VERSION 5.8 ;
BUSBITCHARS "[]" ;
DIVIDERCHAR "/" ;
UNITS
    DATABASE MICRONS 1000 ;
END UNITS

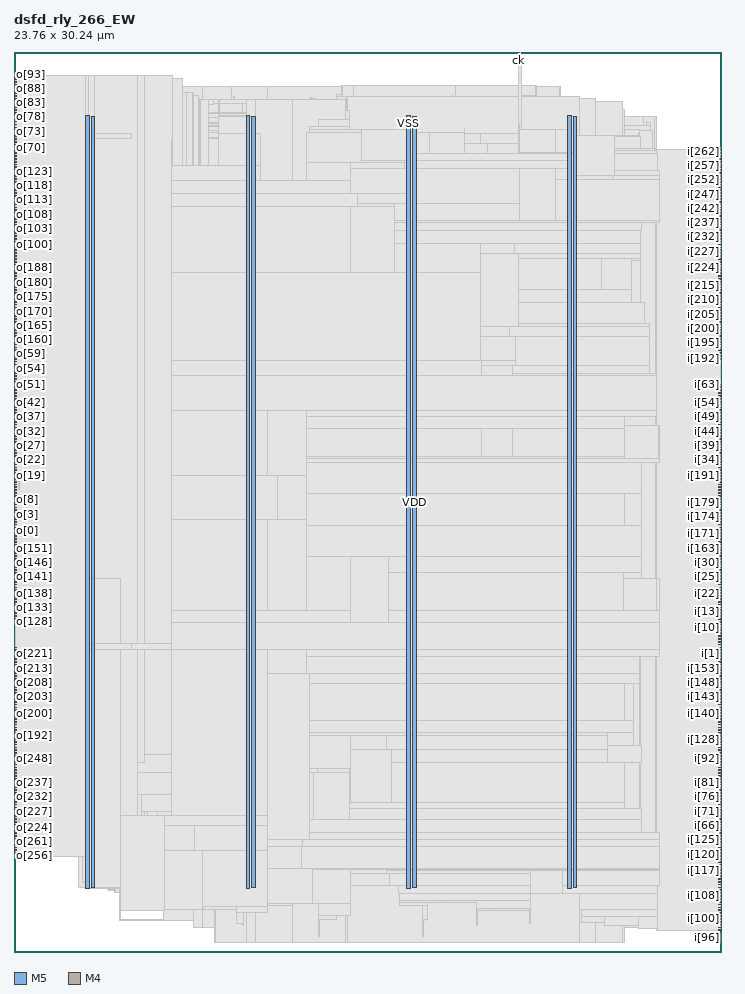
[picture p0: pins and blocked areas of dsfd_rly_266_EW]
MACRO dsfd_rly_266_EW
  FOREIGN dsfd_rly_266_EW 0 0 ;
  CLASS BLOCK ;
  SIZE 23.76 BY 30.24 ;
  PIN ck
    DIRECTION INPUT ;
    USE SIGNAL ;
    PORT
      LAYER M5 ;
        RECT  16.944 30.156 16.968 30.24 ;
    END
  END ck
  PIN i[0]
    DIRECTION INPUT ;
    USE SIGNAL ;
    PORT
      LAYER M4 ;
        RECT  23.676 9.936 23.76 9.96 ;
    END
  END i[0]
  PIN i[100]
    DIRECTION INPUT ;
    USE SIGNAL ;
    PORT
      LAYER M4 ;
        RECT  23.676 1.104 23.76 1.128 ;
    END
  END i[100]
  PIN i[101]
    DIRECTION INPUT ;
    USE SIGNAL ;
    PORT
      LAYER M4 ;
        RECT  23.676 1.2 23.76 1.224 ;
    END
  END i[101]
  PIN i[102]
    DIRECTION INPUT ;
    USE SIGNAL ;
    PORT
      LAYER M4 ;
        RECT  23.676 1.296 23.76 1.32 ;
    END
  END i[102]
  PIN i[103]
    DIRECTION INPUT ;
    USE SIGNAL ;
    PORT
      LAYER M4 ;
        RECT  23.676 1.392 23.76 1.416 ;
    END
  END i[103]
  PIN i[104]
    DIRECTION INPUT ;
    USE SIGNAL ;
    PORT
      LAYER M4 ;
        RECT  23.676 1.488 23.76 1.512 ;
    END
  END i[104]
  PIN i[105]
    DIRECTION INPUT ;
    USE SIGNAL ;
    PORT
      LAYER M4 ;
        RECT  23.676 1.584 23.76 1.608 ;
    END
  END i[105]
  PIN i[106]
    DIRECTION INPUT ;
    USE SIGNAL ;
    PORT
      LAYER M4 ;
        RECT  23.676 1.68 23.76 1.704 ;
    END
  END i[106]
  PIN i[107]
    DIRECTION INPUT ;
    USE SIGNAL ;
    PORT
      LAYER M4 ;
        RECT  23.676 1.776 23.76 1.8 ;
    END
  END i[107]
  PIN i[108]
    DIRECTION INPUT ;
    USE SIGNAL ;
    PORT
      LAYER M4 ;
        RECT  23.676 1.872 23.76 1.896 ;
    END
  END i[108]
  PIN i[109]
    DIRECTION INPUT ;
    USE SIGNAL ;
    PORT
      LAYER M4 ;
        RECT  23.676 1.968 23.76 1.992 ;
    END
  END i[109]
  PIN i[10]
    DIRECTION INPUT ;
    USE SIGNAL ;
    PORT
      LAYER M4 ;
        RECT  23.676 10.896 23.76 10.92 ;
    END
  END i[10]
  PIN i[110]
    DIRECTION INPUT ;
    USE SIGNAL ;
    PORT
      LAYER M4 ;
        RECT  23.676 2.064 23.76 2.088 ;
    END
  END i[110]
  PIN i[111]
    DIRECTION INPUT ;
    USE SIGNAL ;
    PORT
      LAYER M4 ;
        RECT  23.676 2.16 23.76 2.184 ;
    END
  END i[111]
  PIN i[112]
    DIRECTION INPUT ;
    USE SIGNAL ;
    PORT
      LAYER M4 ;
        RECT  23.676 2.256 23.76 2.28 ;
    END
  END i[112]
  PIN i[113]
    DIRECTION INPUT ;
    USE SIGNAL ;
    PORT
      LAYER M4 ;
        RECT  23.676 2.352 23.76 2.376 ;
    END
  END i[113]
  PIN i[114]
    DIRECTION INPUT ;
    USE SIGNAL ;
    PORT
      LAYER M4 ;
        RECT  23.676 2.448 23.76 2.472 ;
    END
  END i[114]
  PIN i[115]
    DIRECTION INPUT ;
    USE SIGNAL ;
    PORT
      LAYER M4 ;
        RECT  23.676 2.544 23.76 2.568 ;
    END
  END i[115]
  PIN i[116]
    DIRECTION INPUT ;
    USE SIGNAL ;
    PORT
      LAYER M4 ;
        RECT  23.676 2.64 23.76 2.664 ;
    END
  END i[116]
  PIN i[117]
    DIRECTION INPUT ;
    USE SIGNAL ;
    PORT
      LAYER M4 ;
        RECT  23.676 2.736 23.76 2.76 ;
    END
  END i[117]
  PIN i[118]
    DIRECTION INPUT ;
    USE SIGNAL ;
    PORT
      LAYER M4 ;
        RECT  23.676 2.832 23.76 2.856 ;
    END
  END i[118]
  PIN i[119]
    DIRECTION INPUT ;
    USE SIGNAL ;
    PORT
      LAYER M4 ;
        RECT  23.676 2.928 23.76 2.952 ;
    END
  END i[119]
  PIN i[11]
    DIRECTION INPUT ;
    USE SIGNAL ;
    PORT
      LAYER M4 ;
        RECT  23.676 10.992 23.76 11.016 ;
    END
  END i[11]
  PIN i[120]
    DIRECTION INPUT ;
    USE SIGNAL ;
    PORT
      LAYER M4 ;
        RECT  23.676 3.024 23.76 3.048 ;
    END
  END i[120]
  PIN i[121]
    DIRECTION INPUT ;
    USE SIGNAL ;
    PORT
      LAYER M4 ;
        RECT  23.676 3.12 23.76 3.144 ;
    END
  END i[121]
  PIN i[122]
    DIRECTION INPUT ;
    USE SIGNAL ;
    PORT
      LAYER M4 ;
        RECT  23.676 3.216 23.76 3.24 ;
    END
  END i[122]
  PIN i[123]
    DIRECTION INPUT ;
    USE SIGNAL ;
    PORT
      LAYER M4 ;
        RECT  23.676 3.312 23.76 3.336 ;
    END
  END i[123]
  PIN i[124]
    DIRECTION INPUT ;
    USE SIGNAL ;
    PORT
      LAYER M4 ;
        RECT  23.676 3.408 23.76 3.432 ;
    END
  END i[124]
  PIN i[125]
    DIRECTION INPUT ;
    USE SIGNAL ;
    PORT
      LAYER M4 ;
        RECT  23.676 3.504 23.76 3.528 ;
    END
  END i[125]
  PIN i[126]
    DIRECTION INPUT ;
    USE SIGNAL ;
    PORT
      LAYER M4 ;
        RECT  23.676 3.6 23.76 3.624 ;
    END
  END i[126]
  PIN i[127]
    DIRECTION INPUT ;
    USE SIGNAL ;
    PORT
      LAYER M4 ;
        RECT  23.676 3.696 23.76 3.72 ;
    END
  END i[127]
  PIN i[128]
    DIRECTION INPUT ;
    USE SIGNAL ;
    PORT
      LAYER M4 ;
        RECT  23.676 6.864 23.76 6.888 ;
    END
  END i[128]
  PIN i[129]
    DIRECTION INPUT ;
    USE SIGNAL ;
    PORT
      LAYER M4 ;
        RECT  23.676 6.96 23.76 6.984 ;
    END
  END i[129]
  PIN i[12]
    DIRECTION INPUT ;
    USE SIGNAL ;
    PORT
      LAYER M4 ;
        RECT  23.676 11.088 23.76 11.112 ;
    END
  END i[12]
  PIN i[130]
    DIRECTION INPUT ;
    USE SIGNAL ;
    PORT
      LAYER M4 ;
        RECT  23.676 7.056 23.76 7.08 ;
    END
  END i[130]
  PIN i[131]
    DIRECTION INPUT ;
    USE SIGNAL ;
    PORT
      LAYER M4 ;
        RECT  23.676 7.152 23.76 7.176 ;
    END
  END i[131]
  PIN i[132]
    DIRECTION INPUT ;
    USE SIGNAL ;
    PORT
      LAYER M4 ;
        RECT  23.676 7.248 23.76 7.272 ;
    END
  END i[132]
  PIN i[133]
    DIRECTION INPUT ;
    USE SIGNAL ;
    PORT
      LAYER M4 ;
        RECT  23.676 7.344 23.76 7.368 ;
    END
  END i[133]
  PIN i[134]
    DIRECTION INPUT ;
    USE SIGNAL ;
    PORT
      LAYER M4 ;
        RECT  23.676 7.44 23.76 7.464 ;
    END
  END i[134]
  PIN i[135]
    DIRECTION INPUT ;
    USE SIGNAL ;
    PORT
      LAYER M4 ;
        RECT  23.676 7.536 23.76 7.56 ;
    END
  END i[135]
  PIN i[136]
    DIRECTION INPUT ;
    USE SIGNAL ;
    PORT
      LAYER M4 ;
        RECT  23.676 7.632 23.76 7.656 ;
    END
  END i[136]
  PIN i[137]
    DIRECTION INPUT ;
    USE SIGNAL ;
    PORT
      LAYER M4 ;
        RECT  23.676 7.728 23.76 7.752 ;
    END
  END i[137]
  PIN i[138]
    DIRECTION INPUT ;
    USE SIGNAL ;
    PORT
      LAYER M4 ;
        RECT  23.676 7.824 23.76 7.848 ;
    END
  END i[138]
  PIN i[139]
    DIRECTION INPUT ;
    USE SIGNAL ;
    PORT
      LAYER M4 ;
        RECT  23.676 7.92 23.76 7.944 ;
    END
  END i[139]
  PIN i[13]
    DIRECTION INPUT ;
    USE SIGNAL ;
    PORT
      LAYER M4 ;
        RECT  23.676 11.184 23.76 11.208 ;
    END
  END i[13]
  PIN i[140]
    DIRECTION INPUT ;
    USE SIGNAL ;
    PORT
      LAYER M4 ;
        RECT  23.676 8.016 23.76 8.04 ;
    END
  END i[140]
  PIN i[141]
    DIRECTION INPUT ;
    USE SIGNAL ;
    PORT
      LAYER M4 ;
        RECT  23.676 8.112 23.76 8.136 ;
    END
  END i[141]
  PIN i[142]
    DIRECTION INPUT ;
    USE SIGNAL ;
    PORT
      LAYER M4 ;
        RECT  23.676 8.208 23.76 8.232 ;
    END
  END i[142]
  PIN i[143]
    DIRECTION INPUT ;
    USE SIGNAL ;
    PORT
      LAYER M4 ;
        RECT  23.676 8.304 23.76 8.328 ;
    END
  END i[143]
  PIN i[144]
    DIRECTION INPUT ;
    USE SIGNAL ;
    PORT
      LAYER M4 ;
        RECT  23.676 8.4 23.76 8.424 ;
    END
  END i[144]
  PIN i[145]
    DIRECTION INPUT ;
    USE SIGNAL ;
    PORT
      LAYER M4 ;
        RECT  23.676 8.496 23.76 8.52 ;
    END
  END i[145]
  PIN i[146]
    DIRECTION INPUT ;
    USE SIGNAL ;
    PORT
      LAYER M4 ;
        RECT  23.676 8.592 23.76 8.616 ;
    END
  END i[146]
  PIN i[147]
    DIRECTION INPUT ;
    USE SIGNAL ;
    PORT
      LAYER M4 ;
        RECT  23.676 8.688 23.76 8.712 ;
    END
  END i[147]
  PIN i[148]
    DIRECTION INPUT ;
    USE SIGNAL ;
    PORT
      LAYER M4 ;
        RECT  23.676 8.784 23.76 8.808 ;
    END
  END i[148]
  PIN i[149]
    DIRECTION INPUT ;
    USE SIGNAL ;
    PORT
      LAYER M4 ;
        RECT  23.676 8.88 23.76 8.904 ;
    END
  END i[149]
  PIN i[14]
    DIRECTION INPUT ;
    USE SIGNAL ;
    PORT
      LAYER M4 ;
        RECT  23.676 11.28 23.76 11.304 ;
    END
  END i[14]
  PIN i[150]
    DIRECTION INPUT ;
    USE SIGNAL ;
    PORT
      LAYER M4 ;
        RECT  23.676 8.976 23.76 9 ;
    END
  END i[150]
  PIN i[151]
    DIRECTION INPUT ;
    USE SIGNAL ;
    PORT
      LAYER M4 ;
        RECT  23.676 9.072 23.76 9.096 ;
    END
  END i[151]
  PIN i[152]
    DIRECTION INPUT ;
    USE SIGNAL ;
    PORT
      LAYER M4 ;
        RECT  23.676 9.168 23.76 9.192 ;
    END
  END i[152]
  PIN i[153]
    DIRECTION INPUT ;
    USE SIGNAL ;
    PORT
      LAYER M4 ;
        RECT  23.676 9.264 23.76 9.288 ;
    END
  END i[153]
  PIN i[154]
    DIRECTION INPUT ;
    USE SIGNAL ;
    PORT
      LAYER M4 ;
        RECT  23.676 9.36 23.76 9.384 ;
    END
  END i[154]
  PIN i[155]
    DIRECTION INPUT ;
    USE SIGNAL ;
    PORT
      LAYER M4 ;
        RECT  23.676 9.456 23.76 9.48 ;
    END
  END i[155]
  PIN i[156]
    DIRECTION INPUT ;
    USE SIGNAL ;
    PORT
      LAYER M4 ;
        RECT  23.676 9.552 23.76 9.576 ;
    END
  END i[156]
  PIN i[157]
    DIRECTION INPUT ;
    USE SIGNAL ;
    PORT
      LAYER M4 ;
        RECT  23.676 9.648 23.76 9.672 ;
    END
  END i[157]
  PIN i[158]
    DIRECTION INPUT ;
    USE SIGNAL ;
    PORT
      LAYER M4 ;
        RECT  23.676 9.744 23.76 9.768 ;
    END
  END i[158]
  PIN i[159]
    DIRECTION INPUT ;
    USE SIGNAL ;
    PORT
      LAYER M4 ;
        RECT  23.676 9.84 23.76 9.864 ;
    END
  END i[159]
  PIN i[15]
    DIRECTION INPUT ;
    USE SIGNAL ;
    PORT
      LAYER M4 ;
        RECT  23.676 11.376 23.76 11.4 ;
    END
  END i[15]
  PIN i[160]
    DIRECTION INPUT ;
    USE SIGNAL ;
    PORT
      LAYER M4 ;
        RECT  23.676 13.008 23.76 13.032 ;
    END
  END i[160]
  PIN i[161]
    DIRECTION INPUT ;
    USE SIGNAL ;
    PORT
      LAYER M4 ;
        RECT  23.676 13.104 23.76 13.128 ;
    END
  END i[161]
  PIN i[162]
    DIRECTION INPUT ;
    USE SIGNAL ;
    PORT
      LAYER M4 ;
        RECT  23.676 13.2 23.76 13.224 ;
    END
  END i[162]
  PIN i[163]
    DIRECTION INPUT ;
    USE SIGNAL ;
    PORT
      LAYER M4 ;
        RECT  23.676 13.296 23.76 13.32 ;
    END
  END i[163]
  PIN i[164]
    DIRECTION INPUT ;
    USE SIGNAL ;
    PORT
      LAYER M4 ;
        RECT  23.676 13.392 23.76 13.416 ;
    END
  END i[164]
  PIN i[165]
    DIRECTION INPUT ;
    USE SIGNAL ;
    PORT
      LAYER M4 ;
        RECT  23.676 13.488 23.76 13.512 ;
    END
  END i[165]
  PIN i[166]
    DIRECTION INPUT ;
    USE SIGNAL ;
    PORT
      LAYER M4 ;
        RECT  23.676 13.584 23.76 13.608 ;
    END
  END i[166]
  PIN i[167]
    DIRECTION INPUT ;
    USE SIGNAL ;
    PORT
      LAYER M4 ;
        RECT  23.676 13.68 23.76 13.704 ;
    END
  END i[167]
  PIN i[168]
    DIRECTION INPUT ;
    USE SIGNAL ;
    PORT
      LAYER M4 ;
        RECT  23.676 13.776 23.76 13.8 ;
    END
  END i[168]
  PIN i[169]
    DIRECTION INPUT ;
    USE SIGNAL ;
    PORT
      LAYER M4 ;
        RECT  23.676 13.872 23.76 13.896 ;
    END
  END i[169]
  PIN i[16]
    DIRECTION INPUT ;
    USE SIGNAL ;
    PORT
      LAYER M4 ;
        RECT  23.676 11.472 23.76 11.496 ;
    END
  END i[16]
  PIN i[170]
    DIRECTION INPUT ;
    USE SIGNAL ;
    PORT
      LAYER M4 ;
        RECT  23.676 13.968 23.76 13.992 ;
    END
  END i[170]
  PIN i[171]
    DIRECTION INPUT ;
    USE SIGNAL ;
    PORT
      LAYER M4 ;
        RECT  23.676 14.064 23.76 14.088 ;
    END
  END i[171]
  PIN i[172]
    DIRECTION INPUT ;
    USE SIGNAL ;
    PORT
      LAYER M4 ;
        RECT  23.676 14.16 23.76 14.184 ;
    END
  END i[172]
  PIN i[173]
    DIRECTION INPUT ;
    USE SIGNAL ;
    PORT
      LAYER M4 ;
        RECT  23.676 14.256 23.76 14.28 ;
    END
  END i[173]
  PIN i[174]
    DIRECTION INPUT ;
    USE SIGNAL ;
    PORT
      LAYER M4 ;
        RECT  23.676 14.352 23.76 14.376 ;
    END
  END i[174]
  PIN i[175]
    DIRECTION INPUT ;
    USE SIGNAL ;
    PORT
      LAYER M4 ;
        RECT  23.676 14.448 23.76 14.472 ;
    END
  END i[175]
  PIN i[176]
    DIRECTION INPUT ;
    USE SIGNAL ;
    PORT
      LAYER M4 ;
        RECT  23.676 14.544 23.76 14.568 ;
    END
  END i[176]
  PIN i[177]
    DIRECTION INPUT ;
    USE SIGNAL ;
    PORT
      LAYER M4 ;
        RECT  23.676 14.64 23.76 14.664 ;
    END
  END i[177]
  PIN i[178]
    DIRECTION INPUT ;
    USE SIGNAL ;
    PORT
      LAYER M4 ;
        RECT  23.676 14.736 23.76 14.76 ;
    END
  END i[178]
  PIN i[179]
    DIRECTION INPUT ;
    USE SIGNAL ;
    PORT
      LAYER M4 ;
        RECT  23.676 14.832 23.76 14.856 ;
    END
  END i[179]
  PIN i[17]
    DIRECTION INPUT ;
    USE SIGNAL ;
    PORT
      LAYER M4 ;
        RECT  23.676 11.568 23.76 11.592 ;
    END
  END i[17]
  PIN i[180]
    DIRECTION INPUT ;
    USE SIGNAL ;
    PORT
      LAYER M4 ;
        RECT  23.676 14.928 23.76 14.952 ;
    END
  END i[180]
  PIN i[181]
    DIRECTION INPUT ;
    USE SIGNAL ;
    PORT
      LAYER M4 ;
        RECT  23.676 15.024 23.76 15.048 ;
    END
  END i[181]
  PIN i[182]
    DIRECTION INPUT ;
    USE SIGNAL ;
    PORT
      LAYER M4 ;
        RECT  23.676 15.12 23.76 15.144 ;
    END
  END i[182]
  PIN i[183]
    DIRECTION INPUT ;
    USE SIGNAL ;
    PORT
      LAYER M4 ;
        RECT  23.676 15.216 23.76 15.24 ;
    END
  END i[183]
  PIN i[184]
    DIRECTION INPUT ;
    USE SIGNAL ;
    PORT
      LAYER M4 ;
        RECT  23.676 15.312 23.76 15.336 ;
    END
  END i[184]
  PIN i[185]
    DIRECTION INPUT ;
    USE SIGNAL ;
    PORT
      LAYER M4 ;
        RECT  23.676 15.408 23.76 15.432 ;
    END
  END i[185]
  PIN i[186]
    DIRECTION INPUT ;
    USE SIGNAL ;
    PORT
      LAYER M4 ;
        RECT  23.676 15.504 23.76 15.528 ;
    END
  END i[186]
  PIN i[187]
    DIRECTION INPUT ;
    USE SIGNAL ;
    PORT
      LAYER M4 ;
        RECT  23.676 15.6 23.76 15.624 ;
    END
  END i[187]
  PIN i[188]
    DIRECTION INPUT ;
    USE SIGNAL ;
    PORT
      LAYER M4 ;
        RECT  23.676 15.696 23.76 15.72 ;
    END
  END i[188]
  PIN i[189]
    DIRECTION INPUT ;
    USE SIGNAL ;
    PORT
      LAYER M4 ;
        RECT  23.676 15.792 23.76 15.816 ;
    END
  END i[189]
  PIN i[18]
    DIRECTION INPUT ;
    USE SIGNAL ;
    PORT
      LAYER M4 ;
        RECT  23.676 11.664 23.76 11.688 ;
    END
  END i[18]
  PIN i[190]
    DIRECTION INPUT ;
    USE SIGNAL ;
    PORT
      LAYER M4 ;
        RECT  23.676 15.888 23.76 15.912 ;
    END
  END i[190]
  PIN i[191]
    DIRECTION INPUT ;
    USE SIGNAL ;
    PORT
      LAYER M4 ;
        RECT  23.676 15.984 23.76 16.008 ;
    END
  END i[191]
  PIN i[192]
    DIRECTION INPUT ;
    USE SIGNAL ;
    PORT
      LAYER M4 ;
        RECT  23.676 19.92 23.76 19.944 ;
    END
  END i[192]
  PIN i[193]
    DIRECTION INPUT ;
    USE SIGNAL ;
    PORT
      LAYER M4 ;
        RECT  23.676 20.016 23.76 20.04 ;
    END
  END i[193]
  PIN i[194]
    DIRECTION INPUT ;
    USE SIGNAL ;
    PORT
      LAYER M4 ;
        RECT  23.676 20.112 23.76 20.136 ;
    END
  END i[194]
  PIN i[195]
    DIRECTION INPUT ;
    USE SIGNAL ;
    PORT
      LAYER M4 ;
        RECT  23.676 20.208 23.76 20.232 ;
    END
  END i[195]
  PIN i[196]
    DIRECTION INPUT ;
    USE SIGNAL ;
    PORT
      LAYER M4 ;
        RECT  23.676 20.304 23.76 20.328 ;
    END
  END i[196]
  PIN i[197]
    DIRECTION INPUT ;
    USE SIGNAL ;
    PORT
      LAYER M4 ;
        RECT  23.676 20.4 23.76 20.424 ;
    END
  END i[197]
  PIN i[198]
    DIRECTION INPUT ;
    USE SIGNAL ;
    PORT
      LAYER M4 ;
        RECT  23.676 20.496 23.76 20.52 ;
    END
  END i[198]
  PIN i[199]
    DIRECTION INPUT ;
    USE SIGNAL ;
    PORT
      LAYER M4 ;
        RECT  23.676 20.592 23.76 20.616 ;
    END
  END i[199]
  PIN i[19]
    DIRECTION INPUT ;
    USE SIGNAL ;
    PORT
      LAYER M4 ;
        RECT  23.676 11.76 23.76 11.784 ;
    END
  END i[19]
  PIN i[1]
    DIRECTION INPUT ;
    USE SIGNAL ;
    PORT
      LAYER M4 ;
        RECT  23.676 10.032 23.76 10.056 ;
    END
  END i[1]
  PIN i[200]
    DIRECTION INPUT ;
    USE SIGNAL ;
    PORT
      LAYER M4 ;
        RECT  23.676 20.688 23.76 20.712 ;
    END
  END i[200]
  PIN i[201]
    DIRECTION INPUT ;
    USE SIGNAL ;
    PORT
      LAYER M4 ;
        RECT  23.676 20.784 23.76 20.808 ;
    END
  END i[201]
  PIN i[202]
    DIRECTION INPUT ;
    USE SIGNAL ;
    PORT
      LAYER M4 ;
        RECT  23.676 20.88 23.76 20.904 ;
    END
  END i[202]
  PIN i[203]
    DIRECTION INPUT ;
    USE SIGNAL ;
    PORT
      LAYER M4 ;
        RECT  23.676 20.976 23.76 21 ;
    END
  END i[203]
  PIN i[204]
    DIRECTION INPUT ;
    USE SIGNAL ;
    PORT
      LAYER M4 ;
        RECT  23.676 21.072 23.76 21.096 ;
    END
  END i[204]
  PIN i[205]
    DIRECTION INPUT ;
    USE SIGNAL ;
    PORT
      LAYER M4 ;
        RECT  23.676 21.168 23.76 21.192 ;
    END
  END i[205]
  PIN i[206]
    DIRECTION INPUT ;
    USE SIGNAL ;
    PORT
      LAYER M4 ;
        RECT  23.676 21.264 23.76 21.288 ;
    END
  END i[206]
  PIN i[207]
    DIRECTION INPUT ;
    USE SIGNAL ;
    PORT
      LAYER M4 ;
        RECT  23.676 21.36 23.76 21.384 ;
    END
  END i[207]
  PIN i[208]
    DIRECTION INPUT ;
    USE SIGNAL ;
    PORT
      LAYER M4 ;
        RECT  23.676 21.456 23.76 21.48 ;
    END
  END i[208]
  PIN i[209]
    DIRECTION INPUT ;
    USE SIGNAL ;
    PORT
      LAYER M4 ;
        RECT  23.676 21.552 23.76 21.576 ;
    END
  END i[209]
  PIN i[20]
    DIRECTION INPUT ;
    USE SIGNAL ;
    PORT
      LAYER M4 ;
        RECT  23.676 11.856 23.76 11.88 ;
    END
  END i[20]
  PIN i[210]
    DIRECTION INPUT ;
    USE SIGNAL ;
    PORT
      LAYER M4 ;
        RECT  23.676 21.648 23.76 21.672 ;
    END
  END i[210]
  PIN i[211]
    DIRECTION INPUT ;
    USE SIGNAL ;
    PORT
      LAYER M4 ;
        RECT  23.676 21.744 23.76 21.768 ;
    END
  END i[211]
  PIN i[212]
    DIRECTION INPUT ;
    USE SIGNAL ;
    PORT
      LAYER M4 ;
        RECT  23.676 21.84 23.76 21.864 ;
    END
  END i[212]
  PIN i[213]
    DIRECTION INPUT ;
    USE SIGNAL ;
    PORT
      LAYER M4 ;
        RECT  23.676 21.936 23.76 21.96 ;
    END
  END i[213]
  PIN i[214]
    DIRECTION INPUT ;
    USE SIGNAL ;
    PORT
      LAYER M4 ;
        RECT  23.676 22.032 23.76 22.056 ;
    END
  END i[214]
  PIN i[215]
    DIRECTION INPUT ;
    USE SIGNAL ;
    PORT
      LAYER M4 ;
        RECT  23.676 22.128 23.76 22.152 ;
    END
  END i[215]
  PIN i[216]
    DIRECTION INPUT ;
    USE SIGNAL ;
    PORT
      LAYER M4 ;
        RECT  23.676 22.224 23.76 22.248 ;
    END
  END i[216]
  PIN i[217]
    DIRECTION INPUT ;
    USE SIGNAL ;
    PORT
      LAYER M4 ;
        RECT  23.676 22.32 23.76 22.344 ;
    END
  END i[217]
  PIN i[218]
    DIRECTION INPUT ;
    USE SIGNAL ;
    PORT
      LAYER M4 ;
        RECT  23.676 22.416 23.76 22.44 ;
    END
  END i[218]
  PIN i[219]
    DIRECTION INPUT ;
    USE SIGNAL ;
    PORT
      LAYER M4 ;
        RECT  23.676 22.512 23.76 22.536 ;
    END
  END i[219]
  PIN i[21]
    DIRECTION INPUT ;
    USE SIGNAL ;
    PORT
      LAYER M4 ;
        RECT  23.676 11.952 23.76 11.976 ;
    END
  END i[21]
  PIN i[220]
    DIRECTION INPUT ;
    USE SIGNAL ;
    PORT
      LAYER M4 ;
        RECT  23.676 22.608 23.76 22.632 ;
    END
  END i[220]
  PIN i[221]
    DIRECTION INPUT ;
    USE SIGNAL ;
    PORT
      LAYER M4 ;
        RECT  23.676 22.704 23.76 22.728 ;
    END
  END i[221]
  PIN i[222]
    DIRECTION INPUT ;
    USE SIGNAL ;
    PORT
      LAYER M4 ;
        RECT  23.676 22.8 23.76 22.824 ;
    END
  END i[222]
  PIN i[223]
    DIRECTION INPUT ;
    USE SIGNAL ;
    PORT
      LAYER M4 ;
        RECT  23.676 22.896 23.76 22.92 ;
    END
  END i[223]
  PIN i[224]
    DIRECTION INPUT ;
    USE SIGNAL ;
    PORT
      LAYER M4 ;
        RECT  23.676 22.992 23.76 23.016 ;
    END
  END i[224]
  PIN i[225]
    DIRECTION INPUT ;
    USE SIGNAL ;
    PORT
      LAYER M4 ;
        RECT  23.676 23.088 23.76 23.112 ;
    END
  END i[225]
  PIN i[226]
    DIRECTION INPUT ;
    USE SIGNAL ;
    PORT
      LAYER M4 ;
        RECT  23.676 23.184 23.76 23.208 ;
    END
  END i[226]
  PIN i[227]
    DIRECTION INPUT ;
    USE SIGNAL ;
    PORT
      LAYER M4 ;
        RECT  23.676 23.28 23.76 23.304 ;
    END
  END i[227]
  PIN i[228]
    DIRECTION INPUT ;
    USE SIGNAL ;
    PORT
      LAYER M4 ;
        RECT  23.676 23.376 23.76 23.4 ;
    END
  END i[228]
  PIN i[229]
    DIRECTION INPUT ;
    USE SIGNAL ;
    PORT
      LAYER M4 ;
        RECT  23.676 23.472 23.76 23.496 ;
    END
  END i[229]
  PIN i[22]
    DIRECTION INPUT ;
    USE SIGNAL ;
    PORT
      LAYER M4 ;
        RECT  23.676 12.048 23.76 12.072 ;
    END
  END i[22]
  PIN i[230]
    DIRECTION INPUT ;
    USE SIGNAL ;
    PORT
      LAYER M4 ;
        RECT  23.676 23.568 23.76 23.592 ;
    END
  END i[230]
  PIN i[231]
    DIRECTION INPUT ;
    USE SIGNAL ;
    PORT
      LAYER M4 ;
        RECT  23.676 23.664 23.76 23.688 ;
    END
  END i[231]
  PIN i[232]
    DIRECTION INPUT ;
    USE SIGNAL ;
    PORT
      LAYER M4 ;
        RECT  23.676 23.76 23.76 23.784 ;
    END
  END i[232]
  PIN i[233]
    DIRECTION INPUT ;
    USE SIGNAL ;
    PORT
      LAYER M4 ;
        RECT  23.676 23.856 23.76 23.88 ;
    END
  END i[233]
  PIN i[234]
    DIRECTION INPUT ;
    USE SIGNAL ;
    PORT
      LAYER M4 ;
        RECT  23.676 23.952 23.76 23.976 ;
    END
  END i[234]
  PIN i[235]
    DIRECTION INPUT ;
    USE SIGNAL ;
    PORT
      LAYER M4 ;
        RECT  23.676 24.048 23.76 24.072 ;
    END
  END i[235]
  PIN i[236]
    DIRECTION INPUT ;
    USE SIGNAL ;
    PORT
      LAYER M4 ;
        RECT  23.676 24.144 23.76 24.168 ;
    END
  END i[236]
  PIN i[237]
    DIRECTION INPUT ;
    USE SIGNAL ;
    PORT
      LAYER M4 ;
        RECT  23.676 24.24 23.76 24.264 ;
    END
  END i[237]
  PIN i[238]
    DIRECTION INPUT ;
    USE SIGNAL ;
    PORT
      LAYER M4 ;
        RECT  23.676 24.336 23.76 24.36 ;
    END
  END i[238]
  PIN i[239]
    DIRECTION INPUT ;
    USE SIGNAL ;
    PORT
      LAYER M4 ;
        RECT  23.676 24.432 23.76 24.456 ;
    END
  END i[239]
  PIN i[23]
    DIRECTION INPUT ;
    USE SIGNAL ;
    PORT
      LAYER M4 ;
        RECT  23.676 12.144 23.76 12.168 ;
    END
  END i[23]
  PIN i[240]
    DIRECTION INPUT ;
    USE SIGNAL ;
    PORT
      LAYER M4 ;
        RECT  23.676 24.528 23.76 24.552 ;
    END
  END i[240]
  PIN i[241]
    DIRECTION INPUT ;
    USE SIGNAL ;
    PORT
      LAYER M4 ;
        RECT  23.676 24.624 23.76 24.648 ;
    END
  END i[241]
  PIN i[242]
    DIRECTION INPUT ;
    USE SIGNAL ;
    PORT
      LAYER M4 ;
        RECT  23.676 24.72 23.76 24.744 ;
    END
  END i[242]
  PIN i[243]
    DIRECTION INPUT ;
    USE SIGNAL ;
    PORT
      LAYER M4 ;
        RECT  23.676 24.816 23.76 24.84 ;
    END
  END i[243]
  PIN i[244]
    DIRECTION INPUT ;
    USE SIGNAL ;
    PORT
      LAYER M4 ;
        RECT  23.676 24.912 23.76 24.936 ;
    END
  END i[244]
  PIN i[245]
    DIRECTION INPUT ;
    USE SIGNAL ;
    PORT
      LAYER M4 ;
        RECT  23.676 25.008 23.76 25.032 ;
    END
  END i[245]
  PIN i[246]
    DIRECTION INPUT ;
    USE SIGNAL ;
    PORT
      LAYER M4 ;
        RECT  23.676 25.104 23.76 25.128 ;
    END
  END i[246]
  PIN i[247]
    DIRECTION INPUT ;
    USE SIGNAL ;
    PORT
      LAYER M4 ;
        RECT  23.676 25.2 23.76 25.224 ;
    END
  END i[247]
  PIN i[248]
    DIRECTION INPUT ;
    USE SIGNAL ;
    PORT
      LAYER M4 ;
        RECT  23.676 25.296 23.76 25.32 ;
    END
  END i[248]
  PIN i[249]
    DIRECTION INPUT ;
    USE SIGNAL ;
    PORT
      LAYER M4 ;
        RECT  23.676 25.392 23.76 25.416 ;
    END
  END i[249]
  PIN i[24]
    DIRECTION INPUT ;
    USE SIGNAL ;
    PORT
      LAYER M4 ;
        RECT  23.676 12.24 23.76 12.264 ;
    END
  END i[24]
  PIN i[250]
    DIRECTION INPUT ;
    USE SIGNAL ;
    PORT
      LAYER M4 ;
        RECT  23.676 25.488 23.76 25.512 ;
    END
  END i[250]
  PIN i[251]
    DIRECTION INPUT ;
    USE SIGNAL ;
    PORT
      LAYER M4 ;
        RECT  23.676 25.584 23.76 25.608 ;
    END
  END i[251]
  PIN i[252]
    DIRECTION INPUT ;
    USE SIGNAL ;
    PORT
      LAYER M4 ;
        RECT  23.676 25.68 23.76 25.704 ;
    END
  END i[252]
  PIN i[253]
    DIRECTION INPUT ;
    USE SIGNAL ;
    PORT
      LAYER M4 ;
        RECT  23.676 25.776 23.76 25.8 ;
    END
  END i[253]
  PIN i[254]
    DIRECTION INPUT ;
    USE SIGNAL ;
    PORT
      LAYER M4 ;
        RECT  23.676 25.872 23.76 25.896 ;
    END
  END i[254]
  PIN i[255]
    DIRECTION INPUT ;
    USE SIGNAL ;
    PORT
      LAYER M4 ;
        RECT  23.676 25.968 23.76 25.992 ;
    END
  END i[255]
  PIN i[256]
    DIRECTION INPUT ;
    USE SIGNAL ;
    PORT
      LAYER M4 ;
        RECT  23.676 26.064 23.76 26.088 ;
    END
  END i[256]
  PIN i[257]
    DIRECTION INPUT ;
    USE SIGNAL ;
    PORT
      LAYER M4 ;
        RECT  23.676 26.16 23.76 26.184 ;
    END
  END i[257]
  PIN i[258]
    DIRECTION INPUT ;
    USE SIGNAL ;
    PORT
      LAYER M4 ;
        RECT  23.676 26.256 23.76 26.28 ;
    END
  END i[258]
  PIN i[259]
    DIRECTION INPUT ;
    USE SIGNAL ;
    PORT
      LAYER M4 ;
        RECT  23.676 26.352 23.76 26.376 ;
    END
  END i[259]
  PIN i[25]
    DIRECTION INPUT ;
    USE SIGNAL ;
    PORT
      LAYER M4 ;
        RECT  23.676 12.336 23.76 12.36 ;
    END
  END i[25]
  PIN i[260]
    DIRECTION INPUT ;
    USE SIGNAL ;
    PORT
      LAYER M4 ;
        RECT  23.676 26.448 23.76 26.472 ;
    END
  END i[260]
  PIN i[261]
    DIRECTION INPUT ;
    USE SIGNAL ;
    PORT
      LAYER M4 ;
        RECT  23.676 26.544 23.76 26.568 ;
    END
  END i[261]
  PIN i[262]
    DIRECTION INPUT ;
    USE SIGNAL ;
    PORT
      LAYER M4 ;
        RECT  23.676 26.64 23.76 26.664 ;
    END
  END i[262]
  PIN i[263]
    DIRECTION INPUT ;
    USE SIGNAL ;
    PORT
      LAYER M4 ;
        RECT  23.676 26.736 23.76 26.76 ;
    END
  END i[263]
  PIN i[264]
    DIRECTION INPUT ;
    USE SIGNAL ;
    PORT
      LAYER M4 ;
        RECT  23.676 26.832 23.76 26.856 ;
    END
  END i[264]
  PIN i[265]
    DIRECTION INPUT ;
    USE SIGNAL ;
    PORT
      LAYER M4 ;
        RECT  23.676 26.928 23.76 26.952 ;
    END
  END i[265]
  PIN i[26]
    DIRECTION INPUT ;
    USE SIGNAL ;
    PORT
      LAYER M4 ;
        RECT  23.676 12.432 23.76 12.456 ;
    END
  END i[26]
  PIN i[27]
    DIRECTION INPUT ;
    USE SIGNAL ;
    PORT
      LAYER M4 ;
        RECT  23.676 12.528 23.76 12.552 ;
    END
  END i[27]
  PIN i[28]
    DIRECTION INPUT ;
    USE SIGNAL ;
    PORT
      LAYER M4 ;
        RECT  23.676 12.624 23.76 12.648 ;
    END
  END i[28]
  PIN i[29]
    DIRECTION INPUT ;
    USE SIGNAL ;
    PORT
      LAYER M4 ;
        RECT  23.676 12.72 23.76 12.744 ;
    END
  END i[29]
  PIN i[2]
    DIRECTION INPUT ;
    USE SIGNAL ;
    PORT
      LAYER M4 ;
        RECT  23.676 10.128 23.76 10.152 ;
    END
  END i[2]
  PIN i[30]
    DIRECTION INPUT ;
    USE SIGNAL ;
    PORT
      LAYER M4 ;
        RECT  23.676 12.816 23.76 12.84 ;
    END
  END i[30]
  PIN i[31]
    DIRECTION INPUT ;
    USE SIGNAL ;
    PORT
      LAYER M4 ;
        RECT  23.676 12.912 23.76 12.936 ;
    END
  END i[31]
  PIN i[32]
    DIRECTION INPUT ;
    USE SIGNAL ;
    PORT
      LAYER M4 ;
        RECT  23.676 16.08 23.76 16.104 ;
    END
  END i[32]
  PIN i[33]
    DIRECTION INPUT ;
    USE SIGNAL ;
    PORT
      LAYER M4 ;
        RECT  23.676 16.176 23.76 16.2 ;
    END
  END i[33]
  PIN i[34]
    DIRECTION INPUT ;
    USE SIGNAL ;
    PORT
      LAYER M4 ;
        RECT  23.676 16.272 23.76 16.296 ;
    END
  END i[34]
  PIN i[35]
    DIRECTION INPUT ;
    USE SIGNAL ;
    PORT
      LAYER M4 ;
        RECT  23.676 16.368 23.76 16.392 ;
    END
  END i[35]
  PIN i[36]
    DIRECTION INPUT ;
    USE SIGNAL ;
    PORT
      LAYER M4 ;
        RECT  23.676 16.464 23.76 16.488 ;
    END
  END i[36]
  PIN i[37]
    DIRECTION INPUT ;
    USE SIGNAL ;
    PORT
      LAYER M4 ;
        RECT  23.676 16.56 23.76 16.584 ;
    END
  END i[37]
  PIN i[38]
    DIRECTION INPUT ;
    USE SIGNAL ;
    PORT
      LAYER M4 ;
        RECT  23.676 16.656 23.76 16.68 ;
    END
  END i[38]
  PIN i[39]
    DIRECTION INPUT ;
    USE SIGNAL ;
    PORT
      LAYER M4 ;
        RECT  23.676 16.752 23.76 16.776 ;
    END
  END i[39]
  PIN i[3]
    DIRECTION INPUT ;
    USE SIGNAL ;
    PORT
      LAYER M4 ;
        RECT  23.676 10.224 23.76 10.248 ;
    END
  END i[3]
  PIN i[40]
    DIRECTION INPUT ;
    USE SIGNAL ;
    PORT
      LAYER M4 ;
        RECT  23.676 16.848 23.76 16.872 ;
    END
  END i[40]
  PIN i[41]
    DIRECTION INPUT ;
    USE SIGNAL ;
    PORT
      LAYER M4 ;
        RECT  23.676 16.944 23.76 16.968 ;
    END
  END i[41]
  PIN i[42]
    DIRECTION INPUT ;
    USE SIGNAL ;
    PORT
      LAYER M4 ;
        RECT  23.676 17.04 23.76 17.064 ;
    END
  END i[42]
  PIN i[43]
    DIRECTION INPUT ;
    USE SIGNAL ;
    PORT
      LAYER M4 ;
        RECT  23.676 17.136 23.76 17.16 ;
    END
  END i[43]
  PIN i[44]
    DIRECTION INPUT ;
    USE SIGNAL ;
    PORT
      LAYER M4 ;
        RECT  23.676 17.232 23.76 17.256 ;
    END
  END i[44]
  PIN i[45]
    DIRECTION INPUT ;
    USE SIGNAL ;
    PORT
      LAYER M4 ;
        RECT  23.676 17.328 23.76 17.352 ;
    END
  END i[45]
  PIN i[46]
    DIRECTION INPUT ;
    USE SIGNAL ;
    PORT
      LAYER M4 ;
        RECT  23.676 17.424 23.76 17.448 ;
    END
  END i[46]
  PIN i[47]
    DIRECTION INPUT ;
    USE SIGNAL ;
    PORT
      LAYER M4 ;
        RECT  23.676 17.52 23.76 17.544 ;
    END
  END i[47]
  PIN i[48]
    DIRECTION INPUT ;
    USE SIGNAL ;
    PORT
      LAYER M4 ;
        RECT  23.676 17.616 23.76 17.64 ;
    END
  END i[48]
  PIN i[49]
    DIRECTION INPUT ;
    USE SIGNAL ;
    PORT
      LAYER M4 ;
        RECT  23.676 17.712 23.76 17.736 ;
    END
  END i[49]
  PIN i[4]
    DIRECTION INPUT ;
    USE SIGNAL ;
    PORT
      LAYER M4 ;
        RECT  23.676 10.32 23.76 10.344 ;
    END
  END i[4]
  PIN i[50]
    DIRECTION INPUT ;
    USE SIGNAL ;
    PORT
      LAYER M4 ;
        RECT  23.676 17.808 23.76 17.832 ;
    END
  END i[50]
  PIN i[51]
    DIRECTION INPUT ;
    USE SIGNAL ;
    PORT
      LAYER M4 ;
        RECT  23.676 17.904 23.76 17.928 ;
    END
  END i[51]
  PIN i[52]
    DIRECTION INPUT ;
    USE SIGNAL ;
    PORT
      LAYER M4 ;
        RECT  23.676 18 23.76 18.024 ;
    END
  END i[52]
  PIN i[53]
    DIRECTION INPUT ;
    USE SIGNAL ;
    PORT
      LAYER M4 ;
        RECT  23.676 18.096 23.76 18.12 ;
    END
  END i[53]
  PIN i[54]
    DIRECTION INPUT ;
    USE SIGNAL ;
    PORT
      LAYER M4 ;
        RECT  23.676 18.192 23.76 18.216 ;
    END
  END i[54]
  PIN i[55]
    DIRECTION INPUT ;
    USE SIGNAL ;
    PORT
      LAYER M4 ;
        RECT  23.676 18.288 23.76 18.312 ;
    END
  END i[55]
  PIN i[56]
    DIRECTION INPUT ;
    USE SIGNAL ;
    PORT
      LAYER M4 ;
        RECT  23.676 18.384 23.76 18.408 ;
    END
  END i[56]
  PIN i[57]
    DIRECTION INPUT ;
    USE SIGNAL ;
    PORT
      LAYER M4 ;
        RECT  23.676 18.48 23.76 18.504 ;
    END
  END i[57]
  PIN i[58]
    DIRECTION INPUT ;
    USE SIGNAL ;
    PORT
      LAYER M4 ;
        RECT  23.676 18.576 23.76 18.6 ;
    END
  END i[58]
  PIN i[59]
    DIRECTION INPUT ;
    USE SIGNAL ;
    PORT
      LAYER M4 ;
        RECT  23.676 18.672 23.76 18.696 ;
    END
  END i[59]
  PIN i[5]
    DIRECTION INPUT ;
    USE SIGNAL ;
    PORT
      LAYER M4 ;
        RECT  23.676 10.416 23.76 10.44 ;
    END
  END i[5]
  PIN i[60]
    DIRECTION INPUT ;
    USE SIGNAL ;
    PORT
      LAYER M4 ;
        RECT  23.676 18.768 23.76 18.792 ;
    END
  END i[60]
  PIN i[61]
    DIRECTION INPUT ;
    USE SIGNAL ;
    PORT
      LAYER M4 ;
        RECT  23.676 18.864 23.76 18.888 ;
    END
  END i[61]
  PIN i[62]
    DIRECTION INPUT ;
    USE SIGNAL ;
    PORT
      LAYER M4 ;
        RECT  23.676 18.96 23.76 18.984 ;
    END
  END i[62]
  PIN i[63]
    DIRECTION INPUT ;
    USE SIGNAL ;
    PORT
      LAYER M4 ;
        RECT  23.676 19.056 23.76 19.08 ;
    END
  END i[63]
  PIN i[64]
    DIRECTION INPUT ;
    USE SIGNAL ;
    PORT
      LAYER M4 ;
        RECT  23.676 3.792 23.76 3.816 ;
    END
  END i[64]
  PIN i[65]
    DIRECTION INPUT ;
    USE SIGNAL ;
    PORT
      LAYER M4 ;
        RECT  23.676 3.888 23.76 3.912 ;
    END
  END i[65]
  PIN i[66]
    DIRECTION INPUT ;
    USE SIGNAL ;
    PORT
      LAYER M4 ;
        RECT  23.676 3.984 23.76 4.008 ;
    END
  END i[66]
  PIN i[67]
    DIRECTION INPUT ;
    USE SIGNAL ;
    PORT
      LAYER M4 ;
        RECT  23.676 4.08 23.76 4.104 ;
    END
  END i[67]
  PIN i[68]
    DIRECTION INPUT ;
    USE SIGNAL ;
    PORT
      LAYER M4 ;
        RECT  23.676 4.176 23.76 4.2 ;
    END
  END i[68]
  PIN i[69]
    DIRECTION INPUT ;
    USE SIGNAL ;
    PORT
      LAYER M4 ;
        RECT  23.676 4.272 23.76 4.296 ;
    END
  END i[69]
  PIN i[6]
    DIRECTION INPUT ;
    USE SIGNAL ;
    PORT
      LAYER M4 ;
        RECT  23.676 10.512 23.76 10.536 ;
    END
  END i[6]
  PIN i[70]
    DIRECTION INPUT ;
    USE SIGNAL ;
    PORT
      LAYER M4 ;
        RECT  23.676 4.368 23.76 4.392 ;
    END
  END i[70]
  PIN i[71]
    DIRECTION INPUT ;
    USE SIGNAL ;
    PORT
      LAYER M4 ;
        RECT  23.676 4.464 23.76 4.488 ;
    END
  END i[71]
  PIN i[72]
    DIRECTION INPUT ;
    USE SIGNAL ;
    PORT
      LAYER M4 ;
        RECT  23.676 4.56 23.76 4.584 ;
    END
  END i[72]
  PIN i[73]
    DIRECTION INPUT ;
    USE SIGNAL ;
    PORT
      LAYER M4 ;
        RECT  23.676 4.656 23.76 4.68 ;
    END
  END i[73]
  PIN i[74]
    DIRECTION INPUT ;
    USE SIGNAL ;
    PORT
      LAYER M4 ;
        RECT  23.676 4.752 23.76 4.776 ;
    END
  END i[74]
  PIN i[75]
    DIRECTION INPUT ;
    USE SIGNAL ;
    PORT
      LAYER M4 ;
        RECT  23.676 4.848 23.76 4.872 ;
    END
  END i[75]
  PIN i[76]
    DIRECTION INPUT ;
    USE SIGNAL ;
    PORT
      LAYER M4 ;
        RECT  23.676 4.944 23.76 4.968 ;
    END
  END i[76]
  PIN i[77]
    DIRECTION INPUT ;
    USE SIGNAL ;
    PORT
      LAYER M4 ;
        RECT  23.676 5.04 23.76 5.064 ;
    END
  END i[77]
  PIN i[78]
    DIRECTION INPUT ;
    USE SIGNAL ;
    PORT
      LAYER M4 ;
        RECT  23.676 5.136 23.76 5.16 ;
    END
  END i[78]
  PIN i[79]
    DIRECTION INPUT ;
    USE SIGNAL ;
    PORT
      LAYER M4 ;
        RECT  23.676 5.232 23.76 5.256 ;
    END
  END i[79]
  PIN i[7]
    DIRECTION INPUT ;
    USE SIGNAL ;
    PORT
      LAYER M4 ;
        RECT  23.676 10.608 23.76 10.632 ;
    END
  END i[7]
  PIN i[80]
    DIRECTION INPUT ;
    USE SIGNAL ;
    PORT
      LAYER M4 ;
        RECT  23.676 5.328 23.76 5.352 ;
    END
  END i[80]
  PIN i[81]
    DIRECTION INPUT ;
    USE SIGNAL ;
    PORT
      LAYER M4 ;
        RECT  23.676 5.424 23.76 5.448 ;
    END
  END i[81]
  PIN i[82]
    DIRECTION INPUT ;
    USE SIGNAL ;
    PORT
      LAYER M4 ;
        RECT  23.676 5.52 23.76 5.544 ;
    END
  END i[82]
  PIN i[83]
    DIRECTION INPUT ;
    USE SIGNAL ;
    PORT
      LAYER M4 ;
        RECT  23.676 5.616 23.76 5.64 ;
    END
  END i[83]
  PIN i[84]
    DIRECTION INPUT ;
    USE SIGNAL ;
    PORT
      LAYER M4 ;
        RECT  23.676 5.712 23.76 5.736 ;
    END
  END i[84]
  PIN i[85]
    DIRECTION INPUT ;
    USE SIGNAL ;
    PORT
      LAYER M4 ;
        RECT  23.676 5.808 23.76 5.832 ;
    END
  END i[85]
  PIN i[86]
    DIRECTION INPUT ;
    USE SIGNAL ;
    PORT
      LAYER M4 ;
        RECT  23.676 5.904 23.76 5.928 ;
    END
  END i[86]
  PIN i[87]
    DIRECTION INPUT ;
    USE SIGNAL ;
    PORT
      LAYER M4 ;
        RECT  23.676 6 23.76 6.024 ;
    END
  END i[87]
  PIN i[88]
    DIRECTION INPUT ;
    USE SIGNAL ;
    PORT
      LAYER M4 ;
        RECT  23.676 6.096 23.76 6.12 ;
    END
  END i[88]
  PIN i[89]
    DIRECTION INPUT ;
    USE SIGNAL ;
    PORT
      LAYER M4 ;
        RECT  23.676 6.192 23.76 6.216 ;
    END
  END i[89]
  PIN i[8]
    DIRECTION INPUT ;
    USE SIGNAL ;
    PORT
      LAYER M4 ;
        RECT  23.676 10.704 23.76 10.728 ;
    END
  END i[8]
  PIN i[90]
    DIRECTION INPUT ;
    USE SIGNAL ;
    PORT
      LAYER M4 ;
        RECT  23.676 6.288 23.76 6.312 ;
    END
  END i[90]
  PIN i[91]
    DIRECTION INPUT ;
    USE SIGNAL ;
    PORT
      LAYER M4 ;
        RECT  23.676 6.384 23.76 6.408 ;
    END
  END i[91]
  PIN i[92]
    DIRECTION INPUT ;
    USE SIGNAL ;
    PORT
      LAYER M4 ;
        RECT  23.676 6.48 23.76 6.504 ;
    END
  END i[92]
  PIN i[93]
    DIRECTION INPUT ;
    USE SIGNAL ;
    PORT
      LAYER M4 ;
        RECT  23.676 6.576 23.76 6.6 ;
    END
  END i[93]
  PIN i[94]
    DIRECTION INPUT ;
    USE SIGNAL ;
    PORT
      LAYER M4 ;
        RECT  23.676 6.672 23.76 6.696 ;
    END
  END i[94]
  PIN i[95]
    DIRECTION INPUT ;
    USE SIGNAL ;
    PORT
      LAYER M4 ;
        RECT  23.676 6.768 23.76 6.792 ;
    END
  END i[95]
  PIN i[96]
    DIRECTION INPUT ;
    USE SIGNAL ;
    PORT
      LAYER M4 ;
        RECT  23.676 0.72 23.76 0.744 ;
    END
  END i[96]
  PIN i[97]
    DIRECTION INPUT ;
    USE SIGNAL ;
    PORT
      LAYER M4 ;
        RECT  23.676 0.816 23.76 0.84 ;
    END
  END i[97]
  PIN i[98]
    DIRECTION INPUT ;
    USE SIGNAL ;
    PORT
      LAYER M4 ;
        RECT  23.676 0.912 23.76 0.936 ;
    END
  END i[98]
  PIN i[99]
    DIRECTION INPUT ;
    USE SIGNAL ;
    PORT
      LAYER M4 ;
        RECT  23.676 1.008 23.76 1.032 ;
    END
  END i[99]
  PIN i[9]
    DIRECTION INPUT ;
    USE SIGNAL ;
    PORT
      LAYER M4 ;
        RECT  23.676 10.8 23.76 10.824 ;
    END
  END i[9]
  PIN o[0]
    DIRECTION OUTPUT ;
    USE SIGNAL ;
    PORT
      LAYER M4 ;
        RECT  0 14.16 0.084 14.184 ;
    END
  END o[0]
  PIN o[100]
    DIRECTION OUTPUT ;
    USE SIGNAL ;
    PORT
      LAYER M4 ;
        RECT  0 23.76 0.084 23.784 ;
    END
  END o[100]
  PIN o[101]
    DIRECTION OUTPUT ;
    USE SIGNAL ;
    PORT
      LAYER M4 ;
        RECT  0 23.856 0.084 23.88 ;
    END
  END o[101]
  PIN o[102]
    DIRECTION OUTPUT ;
    USE SIGNAL ;
    PORT
      LAYER M4 ;
        RECT  0 23.952 0.084 23.976 ;
    END
  END o[102]
  PIN o[103]
    DIRECTION OUTPUT ;
    USE SIGNAL ;
    PORT
      LAYER M4 ;
        RECT  0 24.048 0.084 24.072 ;
    END
  END o[103]
  PIN o[104]
    DIRECTION OUTPUT ;
    USE SIGNAL ;
    PORT
      LAYER M4 ;
        RECT  0 24.144 0.084 24.168 ;
    END
  END o[104]
  PIN o[105]
    DIRECTION OUTPUT ;
    USE SIGNAL ;
    PORT
      LAYER M4 ;
        RECT  0 24.24 0.084 24.264 ;
    END
  END o[105]
  PIN o[106]
    DIRECTION OUTPUT ;
    USE SIGNAL ;
    PORT
      LAYER M4 ;
        RECT  0 24.336 0.084 24.36 ;
    END
  END o[106]
  PIN o[107]
    DIRECTION OUTPUT ;
    USE SIGNAL ;
    PORT
      LAYER M4 ;
        RECT  0 24.432 0.084 24.456 ;
    END
  END o[107]
  PIN o[108]
    DIRECTION OUTPUT ;
    USE SIGNAL ;
    PORT
      LAYER M4 ;
        RECT  0 24.528 0.084 24.552 ;
    END
  END o[108]
  PIN o[109]
    DIRECTION OUTPUT ;
    USE SIGNAL ;
    PORT
      LAYER M4 ;
        RECT  0 24.624 0.084 24.648 ;
    END
  END o[109]
  PIN o[10]
    DIRECTION OUTPUT ;
    USE SIGNAL ;
    PORT
      LAYER M4 ;
        RECT  0 15.12 0.084 15.144 ;
    END
  END o[10]
  PIN o[110]
    DIRECTION OUTPUT ;
    USE SIGNAL ;
    PORT
      LAYER M4 ;
        RECT  0 24.72 0.084 24.744 ;
    END
  END o[110]
  PIN o[111]
    DIRECTION OUTPUT ;
    USE SIGNAL ;
    PORT
      LAYER M4 ;
        RECT  0 24.816 0.084 24.84 ;
    END
  END o[111]
  PIN o[112]
    DIRECTION OUTPUT ;
    USE SIGNAL ;
    PORT
      LAYER M4 ;
        RECT  0 24.912 0.084 24.936 ;
    END
  END o[112]
  PIN o[113]
    DIRECTION OUTPUT ;
    USE SIGNAL ;
    PORT
      LAYER M4 ;
        RECT  0 25.008 0.084 25.032 ;
    END
  END o[113]
  PIN o[114]
    DIRECTION OUTPUT ;
    USE SIGNAL ;
    PORT
      LAYER M4 ;
        RECT  0 25.104 0.084 25.128 ;
    END
  END o[114]
  PIN o[115]
    DIRECTION OUTPUT ;
    USE SIGNAL ;
    PORT
      LAYER M4 ;
        RECT  0 25.2 0.084 25.224 ;
    END
  END o[115]
  PIN o[116]
    DIRECTION OUTPUT ;
    USE SIGNAL ;
    PORT
      LAYER M4 ;
        RECT  0 25.296 0.084 25.32 ;
    END
  END o[116]
  PIN o[117]
    DIRECTION OUTPUT ;
    USE SIGNAL ;
    PORT
      LAYER M4 ;
        RECT  0 25.392 0.084 25.416 ;
    END
  END o[117]
  PIN o[118]
    DIRECTION OUTPUT ;
    USE SIGNAL ;
    PORT
      LAYER M4 ;
        RECT  0 25.488 0.084 25.512 ;
    END
  END o[118]
  PIN o[119]
    DIRECTION OUTPUT ;
    USE SIGNAL ;
    PORT
      LAYER M4 ;
        RECT  0 25.584 0.084 25.608 ;
    END
  END o[119]
  PIN o[11]
    DIRECTION OUTPUT ;
    USE SIGNAL ;
    PORT
      LAYER M4 ;
        RECT  0 15.216 0.084 15.24 ;
    END
  END o[11]
  PIN o[120]
    DIRECTION OUTPUT ;
    USE SIGNAL ;
    PORT
      LAYER M4 ;
        RECT  0 25.68 0.084 25.704 ;
    END
  END o[120]
  PIN o[121]
    DIRECTION OUTPUT ;
    USE SIGNAL ;
    PORT
      LAYER M4 ;
        RECT  0 25.776 0.084 25.8 ;
    END
  END o[121]
  PIN o[122]
    DIRECTION OUTPUT ;
    USE SIGNAL ;
    PORT
      LAYER M4 ;
        RECT  0 25.872 0.084 25.896 ;
    END
  END o[122]
  PIN o[123]
    DIRECTION OUTPUT ;
    USE SIGNAL ;
    PORT
      LAYER M4 ;
        RECT  0 25.968 0.084 25.992 ;
    END
  END o[123]
  PIN o[124]
    DIRECTION OUTPUT ;
    USE SIGNAL ;
    PORT
      LAYER M4 ;
        RECT  0 26.064 0.084 26.088 ;
    END
  END o[124]
  PIN o[125]
    DIRECTION OUTPUT ;
    USE SIGNAL ;
    PORT
      LAYER M4 ;
        RECT  0 26.16 0.084 26.184 ;
    END
  END o[125]
  PIN o[126]
    DIRECTION OUTPUT ;
    USE SIGNAL ;
    PORT
      LAYER M4 ;
        RECT  0 26.256 0.084 26.28 ;
    END
  END o[126]
  PIN o[127]
    DIRECTION OUTPUT ;
    USE SIGNAL ;
    PORT
      LAYER M4 ;
        RECT  0 26.352 0.084 26.376 ;
    END
  END o[127]
  PIN o[128]
    DIRECTION OUTPUT ;
    USE SIGNAL ;
    PORT
      LAYER M4 ;
        RECT  0 11.088 0.084 11.112 ;
    END
  END o[128]
  PIN o[129]
    DIRECTION OUTPUT ;
    USE SIGNAL ;
    PORT
      LAYER M4 ;
        RECT  0 11.184 0.084 11.208 ;
    END
  END o[129]
  PIN o[12]
    DIRECTION OUTPUT ;
    USE SIGNAL ;
    PORT
      LAYER M4 ;
        RECT  0 15.312 0.084 15.336 ;
    END
  END o[12]
  PIN o[130]
    DIRECTION OUTPUT ;
    USE SIGNAL ;
    PORT
      LAYER M4 ;
        RECT  0 11.28 0.084 11.304 ;
    END
  END o[130]
  PIN o[131]
    DIRECTION OUTPUT ;
    USE SIGNAL ;
    PORT
      LAYER M4 ;
        RECT  0 11.376 0.084 11.4 ;
    END
  END o[131]
  PIN o[132]
    DIRECTION OUTPUT ;
    USE SIGNAL ;
    PORT
      LAYER M4 ;
        RECT  0 11.472 0.084 11.496 ;
    END
  END o[132]
  PIN o[133]
    DIRECTION OUTPUT ;
    USE SIGNAL ;
    PORT
      LAYER M4 ;
        RECT  0 11.568 0.084 11.592 ;
    END
  END o[133]
  PIN o[134]
    DIRECTION OUTPUT ;
    USE SIGNAL ;
    PORT
      LAYER M4 ;
        RECT  0 11.664 0.084 11.688 ;
    END
  END o[134]
  PIN o[135]
    DIRECTION OUTPUT ;
    USE SIGNAL ;
    PORT
      LAYER M4 ;
        RECT  0 11.76 0.084 11.784 ;
    END
  END o[135]
  PIN o[136]
    DIRECTION OUTPUT ;
    USE SIGNAL ;
    PORT
      LAYER M4 ;
        RECT  0 11.856 0.084 11.88 ;
    END
  END o[136]
  PIN o[137]
    DIRECTION OUTPUT ;
    USE SIGNAL ;
    PORT
      LAYER M4 ;
        RECT  0 11.952 0.084 11.976 ;
    END
  END o[137]
  PIN o[138]
    DIRECTION OUTPUT ;
    USE SIGNAL ;
    PORT
      LAYER M4 ;
        RECT  0 12.048 0.084 12.072 ;
    END
  END o[138]
  PIN o[139]
    DIRECTION OUTPUT ;
    USE SIGNAL ;
    PORT
      LAYER M4 ;
        RECT  0 12.144 0.084 12.168 ;
    END
  END o[139]
  PIN o[13]
    DIRECTION OUTPUT ;
    USE SIGNAL ;
    PORT
      LAYER M4 ;
        RECT  0 15.408 0.084 15.432 ;
    END
  END o[13]
  PIN o[140]
    DIRECTION OUTPUT ;
    USE SIGNAL ;
    PORT
      LAYER M4 ;
        RECT  0 12.24 0.084 12.264 ;
    END
  END o[140]
  PIN o[141]
    DIRECTION OUTPUT ;
    USE SIGNAL ;
    PORT
      LAYER M4 ;
        RECT  0 12.336 0.084 12.36 ;
    END
  END o[141]
  PIN o[142]
    DIRECTION OUTPUT ;
    USE SIGNAL ;
    PORT
      LAYER M4 ;
        RECT  0 12.432 0.084 12.456 ;
    END
  END o[142]
  PIN o[143]
    DIRECTION OUTPUT ;
    USE SIGNAL ;
    PORT
      LAYER M4 ;
        RECT  0 12.528 0.084 12.552 ;
    END
  END o[143]
  PIN o[144]
    DIRECTION OUTPUT ;
    USE SIGNAL ;
    PORT
      LAYER M4 ;
        RECT  0 12.624 0.084 12.648 ;
    END
  END o[144]
  PIN o[145]
    DIRECTION OUTPUT ;
    USE SIGNAL ;
    PORT
      LAYER M4 ;
        RECT  0 12.72 0.084 12.744 ;
    END
  END o[145]
  PIN o[146]
    DIRECTION OUTPUT ;
    USE SIGNAL ;
    PORT
      LAYER M4 ;
        RECT  0 12.816 0.084 12.84 ;
    END
  END o[146]
  PIN o[147]
    DIRECTION OUTPUT ;
    USE SIGNAL ;
    PORT
      LAYER M4 ;
        RECT  0 12.912 0.084 12.936 ;
    END
  END o[147]
  PIN o[148]
    DIRECTION OUTPUT ;
    USE SIGNAL ;
    PORT
      LAYER M4 ;
        RECT  0 13.008 0.084 13.032 ;
    END
  END o[148]
  PIN o[149]
    DIRECTION OUTPUT ;
    USE SIGNAL ;
    PORT
      LAYER M4 ;
        RECT  0 13.104 0.084 13.128 ;
    END
  END o[149]
  PIN o[14]
    DIRECTION OUTPUT ;
    USE SIGNAL ;
    PORT
      LAYER M4 ;
        RECT  0 15.504 0.084 15.528 ;
    END
  END o[14]
  PIN o[150]
    DIRECTION OUTPUT ;
    USE SIGNAL ;
    PORT
      LAYER M4 ;
        RECT  0 13.2 0.084 13.224 ;
    END
  END o[150]
  PIN o[151]
    DIRECTION OUTPUT ;
    USE SIGNAL ;
    PORT
      LAYER M4 ;
        RECT  0 13.296 0.084 13.32 ;
    END
  END o[151]
  PIN o[152]
    DIRECTION OUTPUT ;
    USE SIGNAL ;
    PORT
      LAYER M4 ;
        RECT  0 13.392 0.084 13.416 ;
    END
  END o[152]
  PIN o[153]
    DIRECTION OUTPUT ;
    USE SIGNAL ;
    PORT
      LAYER M4 ;
        RECT  0 13.488 0.084 13.512 ;
    END
  END o[153]
  PIN o[154]
    DIRECTION OUTPUT ;
    USE SIGNAL ;
    PORT
      LAYER M4 ;
        RECT  0 13.584 0.084 13.608 ;
    END
  END o[154]
  PIN o[155]
    DIRECTION OUTPUT ;
    USE SIGNAL ;
    PORT
      LAYER M4 ;
        RECT  0 13.68 0.084 13.704 ;
    END
  END o[155]
  PIN o[156]
    DIRECTION OUTPUT ;
    USE SIGNAL ;
    PORT
      LAYER M4 ;
        RECT  0 13.776 0.084 13.8 ;
    END
  END o[156]
  PIN o[157]
    DIRECTION OUTPUT ;
    USE SIGNAL ;
    PORT
      LAYER M4 ;
        RECT  0 13.872 0.084 13.896 ;
    END
  END o[157]
  PIN o[158]
    DIRECTION OUTPUT ;
    USE SIGNAL ;
    PORT
      LAYER M4 ;
        RECT  0 13.968 0.084 13.992 ;
    END
  END o[158]
  PIN o[159]
    DIRECTION OUTPUT ;
    USE SIGNAL ;
    PORT
      LAYER M4 ;
        RECT  0 14.064 0.084 14.088 ;
    END
  END o[159]
  PIN o[15]
    DIRECTION OUTPUT ;
    USE SIGNAL ;
    PORT
      LAYER M4 ;
        RECT  0 15.6 0.084 15.624 ;
    END
  END o[15]
  PIN o[160]
    DIRECTION OUTPUT ;
    USE SIGNAL ;
    PORT
      LAYER M4 ;
        RECT  0 20.304 0.084 20.328 ;
    END
  END o[160]
  PIN o[161]
    DIRECTION OUTPUT ;
    USE SIGNAL ;
    PORT
      LAYER M4 ;
        RECT  0 20.4 0.084 20.424 ;
    END
  END o[161]
  PIN o[162]
    DIRECTION OUTPUT ;
    USE SIGNAL ;
    PORT
      LAYER M4 ;
        RECT  0 20.496 0.084 20.52 ;
    END
  END o[162]
  PIN o[163]
    DIRECTION OUTPUT ;
    USE SIGNAL ;
    PORT
      LAYER M4 ;
        RECT  0 20.592 0.084 20.616 ;
    END
  END o[163]
  PIN o[164]
    DIRECTION OUTPUT ;
    USE SIGNAL ;
    PORT
      LAYER M4 ;
        RECT  0 20.688 0.084 20.712 ;
    END
  END o[164]
  PIN o[165]
    DIRECTION OUTPUT ;
    USE SIGNAL ;
    PORT
      LAYER M4 ;
        RECT  0 20.784 0.084 20.808 ;
    END
  END o[165]
  PIN o[166]
    DIRECTION OUTPUT ;
    USE SIGNAL ;
    PORT
      LAYER M4 ;
        RECT  0 20.88 0.084 20.904 ;
    END
  END o[166]
  PIN o[167]
    DIRECTION OUTPUT ;
    USE SIGNAL ;
    PORT
      LAYER M4 ;
        RECT  0 20.976 0.084 21 ;
    END
  END o[167]
  PIN o[168]
    DIRECTION OUTPUT ;
    USE SIGNAL ;
    PORT
      LAYER M4 ;
        RECT  0 21.072 0.084 21.096 ;
    END
  END o[168]
  PIN o[169]
    DIRECTION OUTPUT ;
    USE SIGNAL ;
    PORT
      LAYER M4 ;
        RECT  0 21.168 0.084 21.192 ;
    END
  END o[169]
  PIN o[16]
    DIRECTION OUTPUT ;
    USE SIGNAL ;
    PORT
      LAYER M4 ;
        RECT  0 15.696 0.084 15.72 ;
    END
  END o[16]
  PIN o[170]
    DIRECTION OUTPUT ;
    USE SIGNAL ;
    PORT
      LAYER M4 ;
        RECT  0 21.264 0.084 21.288 ;
    END
  END o[170]
  PIN o[171]
    DIRECTION OUTPUT ;
    USE SIGNAL ;
    PORT
      LAYER M4 ;
        RECT  0 21.36 0.084 21.384 ;
    END
  END o[171]
  PIN o[172]
    DIRECTION OUTPUT ;
    USE SIGNAL ;
    PORT
      LAYER M4 ;
        RECT  0 21.456 0.084 21.48 ;
    END
  END o[172]
  PIN o[173]
    DIRECTION OUTPUT ;
    USE SIGNAL ;
    PORT
      LAYER M4 ;
        RECT  0 21.552 0.084 21.576 ;
    END
  END o[173]
  PIN o[174]
    DIRECTION OUTPUT ;
    USE SIGNAL ;
    PORT
      LAYER M4 ;
        RECT  0 21.648 0.084 21.672 ;
    END
  END o[174]
  PIN o[175]
    DIRECTION OUTPUT ;
    USE SIGNAL ;
    PORT
      LAYER M4 ;
        RECT  0 21.744 0.084 21.768 ;
    END
  END o[175]
  PIN o[176]
    DIRECTION OUTPUT ;
    USE SIGNAL ;
    PORT
      LAYER M4 ;
        RECT  0 21.84 0.084 21.864 ;
    END
  END o[176]
  PIN o[177]
    DIRECTION OUTPUT ;
    USE SIGNAL ;
    PORT
      LAYER M4 ;
        RECT  0 21.936 0.084 21.96 ;
    END
  END o[177]
  PIN o[178]
    DIRECTION OUTPUT ;
    USE SIGNAL ;
    PORT
      LAYER M4 ;
        RECT  0 22.032 0.084 22.056 ;
    END
  END o[178]
  PIN o[179]
    DIRECTION OUTPUT ;
    USE SIGNAL ;
    PORT
      LAYER M4 ;
        RECT  0 22.128 0.084 22.152 ;
    END
  END o[179]
  PIN o[17]
    DIRECTION OUTPUT ;
    USE SIGNAL ;
    PORT
      LAYER M4 ;
        RECT  0 15.792 0.084 15.816 ;
    END
  END o[17]
  PIN o[180]
    DIRECTION OUTPUT ;
    USE SIGNAL ;
    PORT
      LAYER M4 ;
        RECT  0 22.224 0.084 22.248 ;
    END
  END o[180]
  PIN o[181]
    DIRECTION OUTPUT ;
    USE SIGNAL ;
    PORT
      LAYER M4 ;
        RECT  0 22.32 0.084 22.344 ;
    END
  END o[181]
  PIN o[182]
    DIRECTION OUTPUT ;
    USE SIGNAL ;
    PORT
      LAYER M4 ;
        RECT  0 22.416 0.084 22.44 ;
    END
  END o[182]
  PIN o[183]
    DIRECTION OUTPUT ;
    USE SIGNAL ;
    PORT
      LAYER M4 ;
        RECT  0 22.512 0.084 22.536 ;
    END
  END o[183]
  PIN o[184]
    DIRECTION OUTPUT ;
    USE SIGNAL ;
    PORT
      LAYER M4 ;
        RECT  0 22.608 0.084 22.632 ;
    END
  END o[184]
  PIN o[185]
    DIRECTION OUTPUT ;
    USE SIGNAL ;
    PORT
      LAYER M4 ;
        RECT  0 22.704 0.084 22.728 ;
    END
  END o[185]
  PIN o[186]
    DIRECTION OUTPUT ;
    USE SIGNAL ;
    PORT
      LAYER M4 ;
        RECT  0 22.8 0.084 22.824 ;
    END
  END o[186]
  PIN o[187]
    DIRECTION OUTPUT ;
    USE SIGNAL ;
    PORT
      LAYER M4 ;
        RECT  0 22.896 0.084 22.92 ;
    END
  END o[187]
  PIN o[188]
    DIRECTION OUTPUT ;
    USE SIGNAL ;
    PORT
      LAYER M4 ;
        RECT  0 22.992 0.084 23.016 ;
    END
  END o[188]
  PIN o[189]
    DIRECTION OUTPUT ;
    USE SIGNAL ;
    PORT
      LAYER M4 ;
        RECT  0 23.088 0.084 23.112 ;
    END
  END o[189]
  PIN o[18]
    DIRECTION OUTPUT ;
    USE SIGNAL ;
    PORT
      LAYER M4 ;
        RECT  0 15.888 0.084 15.912 ;
    END
  END o[18]
  PIN o[190]
    DIRECTION OUTPUT ;
    USE SIGNAL ;
    PORT
      LAYER M4 ;
        RECT  0 23.184 0.084 23.208 ;
    END
  END o[190]
  PIN o[191]
    DIRECTION OUTPUT ;
    USE SIGNAL ;
    PORT
      LAYER M4 ;
        RECT  0 23.28 0.084 23.304 ;
    END
  END o[191]
  PIN o[192]
    DIRECTION OUTPUT ;
    USE SIGNAL ;
    PORT
      LAYER M4 ;
        RECT  0 7.248 0.084 7.272 ;
    END
  END o[192]
  PIN o[193]
    DIRECTION OUTPUT ;
    USE SIGNAL ;
    PORT
      LAYER M4 ;
        RECT  0 7.344 0.084 7.368 ;
    END
  END o[193]
  PIN o[194]
    DIRECTION OUTPUT ;
    USE SIGNAL ;
    PORT
      LAYER M4 ;
        RECT  0 7.44 0.084 7.464 ;
    END
  END o[194]
  PIN o[195]
    DIRECTION OUTPUT ;
    USE SIGNAL ;
    PORT
      LAYER M4 ;
        RECT  0 7.536 0.084 7.56 ;
    END
  END o[195]
  PIN o[196]
    DIRECTION OUTPUT ;
    USE SIGNAL ;
    PORT
      LAYER M4 ;
        RECT  0 7.632 0.084 7.656 ;
    END
  END o[196]
  PIN o[197]
    DIRECTION OUTPUT ;
    USE SIGNAL ;
    PORT
      LAYER M4 ;
        RECT  0 7.728 0.084 7.752 ;
    END
  END o[197]
  PIN o[198]
    DIRECTION OUTPUT ;
    USE SIGNAL ;
    PORT
      LAYER M4 ;
        RECT  0 7.824 0.084 7.848 ;
    END
  END o[198]
  PIN o[199]
    DIRECTION OUTPUT ;
    USE SIGNAL ;
    PORT
      LAYER M4 ;
        RECT  0 7.92 0.084 7.944 ;
    END
  END o[199]
  PIN o[19]
    DIRECTION OUTPUT ;
    USE SIGNAL ;
    PORT
      LAYER M4 ;
        RECT  0 15.984 0.084 16.008 ;
    END
  END o[19]
  PIN o[1]
    DIRECTION OUTPUT ;
    USE SIGNAL ;
    PORT
      LAYER M4 ;
        RECT  0 14.256 0.084 14.28 ;
    END
  END o[1]
  PIN o[200]
    DIRECTION OUTPUT ;
    USE SIGNAL ;
    PORT
      LAYER M4 ;
        RECT  0 8.016 0.084 8.04 ;
    END
  END o[200]
  PIN o[201]
    DIRECTION OUTPUT ;
    USE SIGNAL ;
    PORT
      LAYER M4 ;
        RECT  0 8.112 0.084 8.136 ;
    END
  END o[201]
  PIN o[202]
    DIRECTION OUTPUT ;
    USE SIGNAL ;
    PORT
      LAYER M4 ;
        RECT  0 8.208 0.084 8.232 ;
    END
  END o[202]
  PIN o[203]
    DIRECTION OUTPUT ;
    USE SIGNAL ;
    PORT
      LAYER M4 ;
        RECT  0 8.304 0.084 8.328 ;
    END
  END o[203]
  PIN o[204]
    DIRECTION OUTPUT ;
    USE SIGNAL ;
    PORT
      LAYER M4 ;
        RECT  0 8.4 0.084 8.424 ;
    END
  END o[204]
  PIN o[205]
    DIRECTION OUTPUT ;
    USE SIGNAL ;
    PORT
      LAYER M4 ;
        RECT  0 8.496 0.084 8.52 ;
    END
  END o[205]
  PIN o[206]
    DIRECTION OUTPUT ;
    USE SIGNAL ;
    PORT
      LAYER M4 ;
        RECT  0 8.592 0.084 8.616 ;
    END
  END o[206]
  PIN o[207]
    DIRECTION OUTPUT ;
    USE SIGNAL ;
    PORT
      LAYER M4 ;
        RECT  0 8.688 0.084 8.712 ;
    END
  END o[207]
  PIN o[208]
    DIRECTION OUTPUT ;
    USE SIGNAL ;
    PORT
      LAYER M4 ;
        RECT  0 8.784 0.084 8.808 ;
    END
  END o[208]
  PIN o[209]
    DIRECTION OUTPUT ;
    USE SIGNAL ;
    PORT
      LAYER M4 ;
        RECT  0 8.88 0.084 8.904 ;
    END
  END o[209]
  PIN o[20]
    DIRECTION OUTPUT ;
    USE SIGNAL ;
    PORT
      LAYER M4 ;
        RECT  0 16.08 0.084 16.104 ;
    END
  END o[20]
  PIN o[210]
    DIRECTION OUTPUT ;
    USE SIGNAL ;
    PORT
      LAYER M4 ;
        RECT  0 8.976 0.084 9 ;
    END
  END o[210]
  PIN o[211]
    DIRECTION OUTPUT ;
    USE SIGNAL ;
    PORT
      LAYER M4 ;
        RECT  0 9.072 0.084 9.096 ;
    END
  END o[211]
  PIN o[212]
    DIRECTION OUTPUT ;
    USE SIGNAL ;
    PORT
      LAYER M4 ;
        RECT  0 9.168 0.084 9.192 ;
    END
  END o[212]
  PIN o[213]
    DIRECTION OUTPUT ;
    USE SIGNAL ;
    PORT
      LAYER M4 ;
        RECT  0 9.264 0.084 9.288 ;
    END
  END o[213]
  PIN o[214]
    DIRECTION OUTPUT ;
    USE SIGNAL ;
    PORT
      LAYER M4 ;
        RECT  0 9.36 0.084 9.384 ;
    END
  END o[214]
  PIN o[215]
    DIRECTION OUTPUT ;
    USE SIGNAL ;
    PORT
      LAYER M4 ;
        RECT  0 9.456 0.084 9.48 ;
    END
  END o[215]
  PIN o[216]
    DIRECTION OUTPUT ;
    USE SIGNAL ;
    PORT
      LAYER M4 ;
        RECT  0 9.552 0.084 9.576 ;
    END
  END o[216]
  PIN o[217]
    DIRECTION OUTPUT ;
    USE SIGNAL ;
    PORT
      LAYER M4 ;
        RECT  0 9.648 0.084 9.672 ;
    END
  END o[217]
  PIN o[218]
    DIRECTION OUTPUT ;
    USE SIGNAL ;
    PORT
      LAYER M4 ;
        RECT  0 9.744 0.084 9.768 ;
    END
  END o[218]
  PIN o[219]
    DIRECTION OUTPUT ;
    USE SIGNAL ;
    PORT
      LAYER M4 ;
        RECT  0 9.84 0.084 9.864 ;
    END
  END o[219]
  PIN o[21]
    DIRECTION OUTPUT ;
    USE SIGNAL ;
    PORT
      LAYER M4 ;
        RECT  0 16.176 0.084 16.2 ;
    END
  END o[21]
  PIN o[220]
    DIRECTION OUTPUT ;
    USE SIGNAL ;
    PORT
      LAYER M4 ;
        RECT  0 9.936 0.084 9.96 ;
    END
  END o[220]
  PIN o[221]
    DIRECTION OUTPUT ;
    USE SIGNAL ;
    PORT
      LAYER M4 ;
        RECT  0 10.032 0.084 10.056 ;
    END
  END o[221]
  PIN o[222]
    DIRECTION OUTPUT ;
    USE SIGNAL ;
    PORT
      LAYER M4 ;
        RECT  0 10.128 0.084 10.152 ;
    END
  END o[222]
  PIN o[223]
    DIRECTION OUTPUT ;
    USE SIGNAL ;
    PORT
      LAYER M4 ;
        RECT  0 10.224 0.084 10.248 ;
    END
  END o[223]
  PIN o[224]
    DIRECTION OUTPUT ;
    USE SIGNAL ;
    PORT
      LAYER M4 ;
        RECT  0 4.176 0.084 4.2 ;
    END
  END o[224]
  PIN o[225]
    DIRECTION OUTPUT ;
    USE SIGNAL ;
    PORT
      LAYER M4 ;
        RECT  0 4.272 0.084 4.296 ;
    END
  END o[225]
  PIN o[226]
    DIRECTION OUTPUT ;
    USE SIGNAL ;
    PORT
      LAYER M4 ;
        RECT  0 4.368 0.084 4.392 ;
    END
  END o[226]
  PIN o[227]
    DIRECTION OUTPUT ;
    USE SIGNAL ;
    PORT
      LAYER M4 ;
        RECT  0 4.464 0.084 4.488 ;
    END
  END o[227]
  PIN o[228]
    DIRECTION OUTPUT ;
    USE SIGNAL ;
    PORT
      LAYER M4 ;
        RECT  0 4.56 0.084 4.584 ;
    END
  END o[228]
  PIN o[229]
    DIRECTION OUTPUT ;
    USE SIGNAL ;
    PORT
      LAYER M4 ;
        RECT  0 4.656 0.084 4.68 ;
    END
  END o[229]
  PIN o[22]
    DIRECTION OUTPUT ;
    USE SIGNAL ;
    PORT
      LAYER M4 ;
        RECT  0 16.272 0.084 16.296 ;
    END
  END o[22]
  PIN o[230]
    DIRECTION OUTPUT ;
    USE SIGNAL ;
    PORT
      LAYER M4 ;
        RECT  0 4.752 0.084 4.776 ;
    END
  END o[230]
  PIN o[231]
    DIRECTION OUTPUT ;
    USE SIGNAL ;
    PORT
      LAYER M4 ;
        RECT  0 4.848 0.084 4.872 ;
    END
  END o[231]
  PIN o[232]
    DIRECTION OUTPUT ;
    USE SIGNAL ;
    PORT
      LAYER M4 ;
        RECT  0 4.944 0.084 4.968 ;
    END
  END o[232]
  PIN o[233]
    DIRECTION OUTPUT ;
    USE SIGNAL ;
    PORT
      LAYER M4 ;
        RECT  0 5.04 0.084 5.064 ;
    END
  END o[233]
  PIN o[234]
    DIRECTION OUTPUT ;
    USE SIGNAL ;
    PORT
      LAYER M4 ;
        RECT  0 5.136 0.084 5.16 ;
    END
  END o[234]
  PIN o[235]
    DIRECTION OUTPUT ;
    USE SIGNAL ;
    PORT
      LAYER M4 ;
        RECT  0 5.232 0.084 5.256 ;
    END
  END o[235]
  PIN o[236]
    DIRECTION OUTPUT ;
    USE SIGNAL ;
    PORT
      LAYER M4 ;
        RECT  0 5.328 0.084 5.352 ;
    END
  END o[236]
  PIN o[237]
    DIRECTION OUTPUT ;
    USE SIGNAL ;
    PORT
      LAYER M4 ;
        RECT  0 5.424 0.084 5.448 ;
    END
  END o[237]
  PIN o[238]
    DIRECTION OUTPUT ;
    USE SIGNAL ;
    PORT
      LAYER M4 ;
        RECT  0 5.52 0.084 5.544 ;
    END
  END o[238]
  PIN o[239]
    DIRECTION OUTPUT ;
    USE SIGNAL ;
    PORT
      LAYER M4 ;
        RECT  0 5.616 0.084 5.64 ;
    END
  END o[239]
  PIN o[23]
    DIRECTION OUTPUT ;
    USE SIGNAL ;
    PORT
      LAYER M4 ;
        RECT  0 16.368 0.084 16.392 ;
    END
  END o[23]
  PIN o[240]
    DIRECTION OUTPUT ;
    USE SIGNAL ;
    PORT
      LAYER M4 ;
        RECT  0 5.712 0.084 5.736 ;
    END
  END o[240]
  PIN o[241]
    DIRECTION OUTPUT ;
    USE SIGNAL ;
    PORT
      LAYER M4 ;
        RECT  0 5.808 0.084 5.832 ;
    END
  END o[241]
  PIN o[242]
    DIRECTION OUTPUT ;
    USE SIGNAL ;
    PORT
      LAYER M4 ;
        RECT  0 5.904 0.084 5.928 ;
    END
  END o[242]
  PIN o[243]
    DIRECTION OUTPUT ;
    USE SIGNAL ;
    PORT
      LAYER M4 ;
        RECT  0 6 0.084 6.024 ;
    END
  END o[243]
  PIN o[244]
    DIRECTION OUTPUT ;
    USE SIGNAL ;
    PORT
      LAYER M4 ;
        RECT  0 6.096 0.084 6.12 ;
    END
  END o[244]
  PIN o[245]
    DIRECTION OUTPUT ;
    USE SIGNAL ;
    PORT
      LAYER M4 ;
        RECT  0 6.192 0.084 6.216 ;
    END
  END o[245]
  PIN o[246]
    DIRECTION OUTPUT ;
    USE SIGNAL ;
    PORT
      LAYER M4 ;
        RECT  0 6.288 0.084 6.312 ;
    END
  END o[246]
  PIN o[247]
    DIRECTION OUTPUT ;
    USE SIGNAL ;
    PORT
      LAYER M4 ;
        RECT  0 6.384 0.084 6.408 ;
    END
  END o[247]
  PIN o[248]
    DIRECTION OUTPUT ;
    USE SIGNAL ;
    PORT
      LAYER M4 ;
        RECT  0 6.48 0.084 6.504 ;
    END
  END o[248]
  PIN o[249]
    DIRECTION OUTPUT ;
    USE SIGNAL ;
    PORT
      LAYER M4 ;
        RECT  0 6.576 0.084 6.6 ;
    END
  END o[249]
  PIN o[24]
    DIRECTION OUTPUT ;
    USE SIGNAL ;
    PORT
      LAYER M4 ;
        RECT  0 16.464 0.084 16.488 ;
    END
  END o[24]
  PIN o[250]
    DIRECTION OUTPUT ;
    USE SIGNAL ;
    PORT
      LAYER M4 ;
        RECT  0 6.672 0.084 6.696 ;
    END
  END o[250]
  PIN o[251]
    DIRECTION OUTPUT ;
    USE SIGNAL ;
    PORT
      LAYER M4 ;
        RECT  0 6.768 0.084 6.792 ;
    END
  END o[251]
  PIN o[252]
    DIRECTION OUTPUT ;
    USE SIGNAL ;
    PORT
      LAYER M4 ;
        RECT  0 6.864 0.084 6.888 ;
    END
  END o[252]
  PIN o[253]
    DIRECTION OUTPUT ;
    USE SIGNAL ;
    PORT
      LAYER M4 ;
        RECT  0 6.96 0.084 6.984 ;
    END
  END o[253]
  PIN o[254]
    DIRECTION OUTPUT ;
    USE SIGNAL ;
    PORT
      LAYER M4 ;
        RECT  0 7.056 0.084 7.08 ;
    END
  END o[254]
  PIN o[255]
    DIRECTION OUTPUT ;
    USE SIGNAL ;
    PORT
      LAYER M4 ;
        RECT  0 7.152 0.084 7.176 ;
    END
  END o[255]
  PIN o[256]
    DIRECTION OUTPUT ;
    USE SIGNAL ;
    PORT
      LAYER M4 ;
        RECT  0 3.216 0.084 3.24 ;
    END
  END o[256]
  PIN o[257]
    DIRECTION OUTPUT ;
    USE SIGNAL ;
    PORT
      LAYER M4 ;
        RECT  0 3.312 0.084 3.336 ;
    END
  END o[257]
  PIN o[258]
    DIRECTION OUTPUT ;
    USE SIGNAL ;
    PORT
      LAYER M4 ;
        RECT  0 3.408 0.084 3.432 ;
    END
  END o[258]
  PIN o[259]
    DIRECTION OUTPUT ;
    USE SIGNAL ;
    PORT
      LAYER M4 ;
        RECT  0 3.504 0.084 3.528 ;
    END
  END o[259]
  PIN o[25]
    DIRECTION OUTPUT ;
    USE SIGNAL ;
    PORT
      LAYER M4 ;
        RECT  0 16.56 0.084 16.584 ;
    END
  END o[25]
  PIN o[260]
    DIRECTION OUTPUT ;
    USE SIGNAL ;
    PORT
      LAYER M4 ;
        RECT  0 3.6 0.084 3.624 ;
    END
  END o[260]
  PIN o[261]
    DIRECTION OUTPUT ;
    USE SIGNAL ;
    PORT
      LAYER M4 ;
        RECT  0 3.696 0.084 3.72 ;
    END
  END o[261]
  PIN o[262]
    DIRECTION OUTPUT ;
    USE SIGNAL ;
    PORT
      LAYER M4 ;
        RECT  0 3.792 0.084 3.816 ;
    END
  END o[262]
  PIN o[263]
    DIRECTION OUTPUT ;
    USE SIGNAL ;
    PORT
      LAYER M4 ;
        RECT  0 3.888 0.084 3.912 ;
    END
  END o[263]
  PIN o[264]
    DIRECTION OUTPUT ;
    USE SIGNAL ;
    PORT
      LAYER M4 ;
        RECT  0 3.984 0.084 4.008 ;
    END
  END o[264]
  PIN o[265]
    DIRECTION OUTPUT ;
    USE SIGNAL ;
    PORT
      LAYER M4 ;
        RECT  0 4.08 0.084 4.104 ;
    END
  END o[265]
  PIN o[26]
    DIRECTION OUTPUT ;
    USE SIGNAL ;
    PORT
      LAYER M4 ;
        RECT  0 16.656 0.084 16.68 ;
    END
  END o[26]
  PIN o[27]
    DIRECTION OUTPUT ;
    USE SIGNAL ;
    PORT
      LAYER M4 ;
        RECT  0 16.752 0.084 16.776 ;
    END
  END o[27]
  PIN o[28]
    DIRECTION OUTPUT ;
    USE SIGNAL ;
    PORT
      LAYER M4 ;
        RECT  0 16.848 0.084 16.872 ;
    END
  END o[28]
  PIN o[29]
    DIRECTION OUTPUT ;
    USE SIGNAL ;
    PORT
      LAYER M4 ;
        RECT  0 16.944 0.084 16.968 ;
    END
  END o[29]
  PIN o[2]
    DIRECTION OUTPUT ;
    USE SIGNAL ;
    PORT
      LAYER M4 ;
        RECT  0 14.352 0.084 14.376 ;
    END
  END o[2]
  PIN o[30]
    DIRECTION OUTPUT ;
    USE SIGNAL ;
    PORT
      LAYER M4 ;
        RECT  0 17.04 0.084 17.064 ;
    END
  END o[30]
  PIN o[31]
    DIRECTION OUTPUT ;
    USE SIGNAL ;
    PORT
      LAYER M4 ;
        RECT  0 17.136 0.084 17.16 ;
    END
  END o[31]
  PIN o[32]
    DIRECTION OUTPUT ;
    USE SIGNAL ;
    PORT
      LAYER M4 ;
        RECT  0 17.232 0.084 17.256 ;
    END
  END o[32]
  PIN o[33]
    DIRECTION OUTPUT ;
    USE SIGNAL ;
    PORT
      LAYER M4 ;
        RECT  0 17.328 0.084 17.352 ;
    END
  END o[33]
  PIN o[34]
    DIRECTION OUTPUT ;
    USE SIGNAL ;
    PORT
      LAYER M4 ;
        RECT  0 17.424 0.084 17.448 ;
    END
  END o[34]
  PIN o[35]
    DIRECTION OUTPUT ;
    USE SIGNAL ;
    PORT
      LAYER M4 ;
        RECT  0 17.52 0.084 17.544 ;
    END
  END o[35]
  PIN o[36]
    DIRECTION OUTPUT ;
    USE SIGNAL ;
    PORT
      LAYER M4 ;
        RECT  0 17.616 0.084 17.64 ;
    END
  END o[36]
  PIN o[37]
    DIRECTION OUTPUT ;
    USE SIGNAL ;
    PORT
      LAYER M4 ;
        RECT  0 17.712 0.084 17.736 ;
    END
  END o[37]
  PIN o[38]
    DIRECTION OUTPUT ;
    USE SIGNAL ;
    PORT
      LAYER M4 ;
        RECT  0 17.808 0.084 17.832 ;
    END
  END o[38]
  PIN o[39]
    DIRECTION OUTPUT ;
    USE SIGNAL ;
    PORT
      LAYER M4 ;
        RECT  0 17.904 0.084 17.928 ;
    END
  END o[39]
  PIN o[3]
    DIRECTION OUTPUT ;
    USE SIGNAL ;
    PORT
      LAYER M4 ;
        RECT  0 14.448 0.084 14.472 ;
    END
  END o[3]
  PIN o[40]
    DIRECTION OUTPUT ;
    USE SIGNAL ;
    PORT
      LAYER M4 ;
        RECT  0 18 0.084 18.024 ;
    END
  END o[40]
  PIN o[41]
    DIRECTION OUTPUT ;
    USE SIGNAL ;
    PORT
      LAYER M4 ;
        RECT  0 18.096 0.084 18.12 ;
    END
  END o[41]
  PIN o[42]
    DIRECTION OUTPUT ;
    USE SIGNAL ;
    PORT
      LAYER M4 ;
        RECT  0 18.192 0.084 18.216 ;
    END
  END o[42]
  PIN o[43]
    DIRECTION OUTPUT ;
    USE SIGNAL ;
    PORT
      LAYER M4 ;
        RECT  0 18.288 0.084 18.312 ;
    END
  END o[43]
  PIN o[44]
    DIRECTION OUTPUT ;
    USE SIGNAL ;
    PORT
      LAYER M4 ;
        RECT  0 18.384 0.084 18.408 ;
    END
  END o[44]
  PIN o[45]
    DIRECTION OUTPUT ;
    USE SIGNAL ;
    PORT
      LAYER M4 ;
        RECT  0 18.48 0.084 18.504 ;
    END
  END o[45]
  PIN o[46]
    DIRECTION OUTPUT ;
    USE SIGNAL ;
    PORT
      LAYER M4 ;
        RECT  0 18.576 0.084 18.6 ;
    END
  END o[46]
  PIN o[47]
    DIRECTION OUTPUT ;
    USE SIGNAL ;
    PORT
      LAYER M4 ;
        RECT  0 18.672 0.084 18.696 ;
    END
  END o[47]
  PIN o[48]
    DIRECTION OUTPUT ;
    USE SIGNAL ;
    PORT
      LAYER M4 ;
        RECT  0 18.768 0.084 18.792 ;
    END
  END o[48]
  PIN o[49]
    DIRECTION OUTPUT ;
    USE SIGNAL ;
    PORT
      LAYER M4 ;
        RECT  0 18.864 0.084 18.888 ;
    END
  END o[49]
  PIN o[4]
    DIRECTION OUTPUT ;
    USE SIGNAL ;
    PORT
      LAYER M4 ;
        RECT  0 14.544 0.084 14.568 ;
    END
  END o[4]
  PIN o[50]
    DIRECTION OUTPUT ;
    USE SIGNAL ;
    PORT
      LAYER M4 ;
        RECT  0 18.96 0.084 18.984 ;
    END
  END o[50]
  PIN o[51]
    DIRECTION OUTPUT ;
    USE SIGNAL ;
    PORT
      LAYER M4 ;
        RECT  0 19.056 0.084 19.08 ;
    END
  END o[51]
  PIN o[52]
    DIRECTION OUTPUT ;
    USE SIGNAL ;
    PORT
      LAYER M4 ;
        RECT  0 19.152 0.084 19.176 ;
    END
  END o[52]
  PIN o[53]
    DIRECTION OUTPUT ;
    USE SIGNAL ;
    PORT
      LAYER M4 ;
        RECT  0 19.248 0.084 19.272 ;
    END
  END o[53]
  PIN o[54]
    DIRECTION OUTPUT ;
    USE SIGNAL ;
    PORT
      LAYER M4 ;
        RECT  0 19.344 0.084 19.368 ;
    END
  END o[54]
  PIN o[55]
    DIRECTION OUTPUT ;
    USE SIGNAL ;
    PORT
      LAYER M4 ;
        RECT  0 19.44 0.084 19.464 ;
    END
  END o[55]
  PIN o[56]
    DIRECTION OUTPUT ;
    USE SIGNAL ;
    PORT
      LAYER M4 ;
        RECT  0 19.536 0.084 19.56 ;
    END
  END o[56]
  PIN o[57]
    DIRECTION OUTPUT ;
    USE SIGNAL ;
    PORT
      LAYER M4 ;
        RECT  0 19.632 0.084 19.656 ;
    END
  END o[57]
  PIN o[58]
    DIRECTION OUTPUT ;
    USE SIGNAL ;
    PORT
      LAYER M4 ;
        RECT  0 19.728 0.084 19.752 ;
    END
  END o[58]
  PIN o[59]
    DIRECTION OUTPUT ;
    USE SIGNAL ;
    PORT
      LAYER M4 ;
        RECT  0 19.824 0.084 19.848 ;
    END
  END o[59]
  PIN o[5]
    DIRECTION OUTPUT ;
    USE SIGNAL ;
    PORT
      LAYER M4 ;
        RECT  0 14.64 0.084 14.664 ;
    END
  END o[5]
  PIN o[60]
    DIRECTION OUTPUT ;
    USE SIGNAL ;
    PORT
      LAYER M4 ;
        RECT  0 19.92 0.084 19.944 ;
    END
  END o[60]
  PIN o[61]
    DIRECTION OUTPUT ;
    USE SIGNAL ;
    PORT
      LAYER M4 ;
        RECT  0 20.016 0.084 20.04 ;
    END
  END o[61]
  PIN o[62]
    DIRECTION OUTPUT ;
    USE SIGNAL ;
    PORT
      LAYER M4 ;
        RECT  0 20.112 0.084 20.136 ;
    END
  END o[62]
  PIN o[63]
    DIRECTION OUTPUT ;
    USE SIGNAL ;
    PORT
      LAYER M4 ;
        RECT  0 20.208 0.084 20.232 ;
    END
  END o[63]
  PIN o[64]
    DIRECTION OUTPUT ;
    USE SIGNAL ;
    PORT
      LAYER M4 ;
        RECT  0 26.448 0.084 26.472 ;
    END
  END o[64]
  PIN o[65]
    DIRECTION OUTPUT ;
    USE SIGNAL ;
    PORT
      LAYER M4 ;
        RECT  0 26.544 0.084 26.568 ;
    END
  END o[65]
  PIN o[66]
    DIRECTION OUTPUT ;
    USE SIGNAL ;
    PORT
      LAYER M4 ;
        RECT  0 26.64 0.084 26.664 ;
    END
  END o[66]
  PIN o[67]
    DIRECTION OUTPUT ;
    USE SIGNAL ;
    PORT
      LAYER M4 ;
        RECT  0 26.736 0.084 26.76 ;
    END
  END o[67]
  PIN o[68]
    DIRECTION OUTPUT ;
    USE SIGNAL ;
    PORT
      LAYER M4 ;
        RECT  0 26.832 0.084 26.856 ;
    END
  END o[68]
  PIN o[69]
    DIRECTION OUTPUT ;
    USE SIGNAL ;
    PORT
      LAYER M4 ;
        RECT  0 26.928 0.084 26.952 ;
    END
  END o[69]
  PIN o[6]
    DIRECTION OUTPUT ;
    USE SIGNAL ;
    PORT
      LAYER M4 ;
        RECT  0 14.736 0.084 14.76 ;
    END
  END o[6]
  PIN o[70]
    DIRECTION OUTPUT ;
    USE SIGNAL ;
    PORT
      LAYER M4 ;
        RECT  0 27.024 0.084 27.048 ;
    END
  END o[70]
  PIN o[71]
    DIRECTION OUTPUT ;
    USE SIGNAL ;
    PORT
      LAYER M4 ;
        RECT  0 27.12 0.084 27.144 ;
    END
  END o[71]
  PIN o[72]
    DIRECTION OUTPUT ;
    USE SIGNAL ;
    PORT
      LAYER M4 ;
        RECT  0 27.216 0.084 27.24 ;
    END
  END o[72]
  PIN o[73]
    DIRECTION OUTPUT ;
    USE SIGNAL ;
    PORT
      LAYER M4 ;
        RECT  0 27.312 0.084 27.336 ;
    END
  END o[73]
  PIN o[74]
    DIRECTION OUTPUT ;
    USE SIGNAL ;
    PORT
      LAYER M4 ;
        RECT  0 27.408 0.084 27.432 ;
    END
  END o[74]
  PIN o[75]
    DIRECTION OUTPUT ;
    USE SIGNAL ;
    PORT
      LAYER M4 ;
        RECT  0 27.504 0.084 27.528 ;
    END
  END o[75]
  PIN o[76]
    DIRECTION OUTPUT ;
    USE SIGNAL ;
    PORT
      LAYER M4 ;
        RECT  0 27.6 0.084 27.624 ;
    END
  END o[76]
  PIN o[77]
    DIRECTION OUTPUT ;
    USE SIGNAL ;
    PORT
      LAYER M4 ;
        RECT  0 27.696 0.084 27.72 ;
    END
  END o[77]
  PIN o[78]
    DIRECTION OUTPUT ;
    USE SIGNAL ;
    PORT
      LAYER M4 ;
        RECT  0 27.792 0.084 27.816 ;
    END
  END o[78]
  PIN o[79]
    DIRECTION OUTPUT ;
    USE SIGNAL ;
    PORT
      LAYER M4 ;
        RECT  0 27.888 0.084 27.912 ;
    END
  END o[79]
  PIN o[7]
    DIRECTION OUTPUT ;
    USE SIGNAL ;
    PORT
      LAYER M4 ;
        RECT  0 14.832 0.084 14.856 ;
    END
  END o[7]
  PIN o[80]
    DIRECTION OUTPUT ;
    USE SIGNAL ;
    PORT
      LAYER M4 ;
        RECT  0 27.984 0.084 28.008 ;
    END
  END o[80]
  PIN o[81]
    DIRECTION OUTPUT ;
    USE SIGNAL ;
    PORT
      LAYER M4 ;
        RECT  0 28.08 0.084 28.104 ;
    END
  END o[81]
  PIN o[82]
    DIRECTION OUTPUT ;
    USE SIGNAL ;
    PORT
      LAYER M4 ;
        RECT  0 28.176 0.084 28.2 ;
    END
  END o[82]
  PIN o[83]
    DIRECTION OUTPUT ;
    USE SIGNAL ;
    PORT
      LAYER M4 ;
        RECT  0 28.272 0.084 28.296 ;
    END
  END o[83]
  PIN o[84]
    DIRECTION OUTPUT ;
    USE SIGNAL ;
    PORT
      LAYER M4 ;
        RECT  0 28.368 0.084 28.392 ;
    END
  END o[84]
  PIN o[85]
    DIRECTION OUTPUT ;
    USE SIGNAL ;
    PORT
      LAYER M4 ;
        RECT  0 28.464 0.084 28.488 ;
    END
  END o[85]
  PIN o[86]
    DIRECTION OUTPUT ;
    USE SIGNAL ;
    PORT
      LAYER M4 ;
        RECT  0 28.56 0.084 28.584 ;
    END
  END o[86]
  PIN o[87]
    DIRECTION OUTPUT ;
    USE SIGNAL ;
    PORT
      LAYER M4 ;
        RECT  0 28.656 0.084 28.68 ;
    END
  END o[87]
  PIN o[88]
    DIRECTION OUTPUT ;
    USE SIGNAL ;
    PORT
      LAYER M4 ;
        RECT  0 28.752 0.084 28.776 ;
    END
  END o[88]
  PIN o[89]
    DIRECTION OUTPUT ;
    USE SIGNAL ;
    PORT
      LAYER M4 ;
        RECT  0 28.848 0.084 28.872 ;
    END
  END o[89]
  PIN o[8]
    DIRECTION OUTPUT ;
    USE SIGNAL ;
    PORT
      LAYER M4 ;
        RECT  0 14.928 0.084 14.952 ;
    END
  END o[8]
  PIN o[90]
    DIRECTION OUTPUT ;
    USE SIGNAL ;
    PORT
      LAYER M4 ;
        RECT  0 28.944 0.084 28.968 ;
    END
  END o[90]
  PIN o[91]
    DIRECTION OUTPUT ;
    USE SIGNAL ;
    PORT
      LAYER M4 ;
        RECT  0 29.04 0.084 29.064 ;
    END
  END o[91]
  PIN o[92]
    DIRECTION OUTPUT ;
    USE SIGNAL ;
    PORT
      LAYER M4 ;
        RECT  0 29.136 0.084 29.16 ;
    END
  END o[92]
  PIN o[93]
    DIRECTION OUTPUT ;
    USE SIGNAL ;
    PORT
      LAYER M4 ;
        RECT  0 29.232 0.084 29.256 ;
    END
  END o[93]
  PIN o[94]
    DIRECTION OUTPUT ;
    USE SIGNAL ;
    PORT
      LAYER M4 ;
        RECT  0 29.328 0.084 29.352 ;
    END
  END o[94]
  PIN o[95]
    DIRECTION OUTPUT ;
    USE SIGNAL ;
    PORT
      LAYER M4 ;
        RECT  0 29.424 0.084 29.448 ;
    END
  END o[95]
  PIN o[96]
    DIRECTION OUTPUT ;
    USE SIGNAL ;
    PORT
      LAYER M4 ;
        RECT  0 23.376 0.084 23.4 ;
    END
  END o[96]
  PIN o[97]
    DIRECTION OUTPUT ;
    USE SIGNAL ;
    PORT
      LAYER M4 ;
        RECT  0 23.472 0.084 23.496 ;
    END
  END o[97]
  PIN o[98]
    DIRECTION OUTPUT ;
    USE SIGNAL ;
    PORT
      LAYER M4 ;
        RECT  0 23.568 0.084 23.592 ;
    END
  END o[98]
  PIN o[99]
    DIRECTION OUTPUT ;
    USE SIGNAL ;
    PORT
      LAYER M4 ;
        RECT  0 23.664 0.084 23.688 ;
    END
  END o[99]
  PIN o[9]
    DIRECTION OUTPUT ;
    USE SIGNAL ;
    PORT
      LAYER M4 ;
        RECT  0 15.024 0.084 15.048 ;
    END
  END o[9]
  PIN rs
    DIRECTION INPUT ;
    USE SIGNAL ;
    PORT
      LAYER M5 ;
        RECT  17.04 30.156 17.064 30.24 ;
    END
  END rs
  PIN VDD
    DIRECTION INOUT ;
    USE POWER ;
    PORT
      LAYER M5 ;
        RECT  18.792 2.151 18.912 28.089 ;
        RECT  13.392 2.151 13.512 28.089 ;
        RECT  7.992 2.151 8.112 28.089 ;
        RECT  2.592 2.151 2.712 28.089 ;
    END
  END VDD
  PIN VSS
    DIRECTION INOUT ;
    USE GROUND ;
    PORT
      LAYER M5 ;
        RECT  18.6 2.137 18.72 28.103 ;
        RECT  13.2 2.137 13.32 28.103 ;
        RECT  7.8 2.137 7.92 28.103 ;
        RECT  2.4 2.137 2.52 28.103 ;
    END
  END VSS
  # OT_OBS_CLOSED layer=M5 d_um=1.536 added=61
  OBS
    LAYER RVTN ;
     RECT  2.16 2.16 21.6 2.295 ;
     RECT  2.16 2.565 21.6 2.835 ;
     RECT  2.16 3.105 21.6 3.375 ;
     RECT  2.16 3.645 21.6 3.915 ;
     RECT  2.16 4.185 21.6 4.455 ;
     RECT  2.16 4.725 21.6 4.995 ;
     RECT  2.16 5.265 21.6 5.535 ;
     RECT  2.16 5.805 21.6 6.075 ;
     RECT  2.16 6.345 21.6 6.615 ;
     RECT  2.16 6.885 21.6 7.155 ;
     RECT  2.16 7.425 21.6 7.695 ;
     RECT  2.16 7.965 21.6 8.235 ;
     RECT  2.16 8.505 21.6 8.775 ;
     RECT  2.16 9.045 21.6 9.315 ;
     RECT  2.16 9.585 21.6 9.855 ;
     RECT  2.16 10.125 21.6 10.395 ;
     RECT  2.16 10.665 21.6 10.935 ;
     RECT  2.16 11.205 21.6 11.475 ;
     RECT  2.16 11.745 21.6 12.015 ;
     RECT  2.16 12.285 21.6 12.555 ;
     RECT  2.16 12.825 21.6 13.095 ;
     RECT  2.16 13.365 21.6 13.635 ;
     RECT  2.16 13.905 21.6 14.175 ;
     RECT  2.16 14.445 21.6 14.715 ;
     RECT  2.16 14.985 21.6 15.255 ;
     RECT  2.16 15.525 21.6 15.795 ;
     RECT  2.16 16.065 21.6 16.335 ;
     RECT  2.16 16.605 21.6 16.875 ;
     RECT  2.16 17.145 21.6 17.415 ;
     RECT  2.16 17.685 21.6 17.955 ;
     RECT  2.16 18.225 21.6 18.495 ;
     RECT  2.16 18.765 21.6 19.035 ;
     RECT  2.16 19.305 21.6 19.575 ;
     RECT  2.16 19.845 21.6 20.115 ;
     RECT  2.16 20.385 21.6 20.655 ;
     RECT  2.16 20.925 21.6 21.195 ;
     RECT  2.16 21.465 21.6 21.735 ;
     RECT  2.16 22.005 21.6 22.275 ;
     RECT  2.16 22.545 21.6 22.815 ;
     RECT  2.16 23.085 21.6 23.355 ;
     RECT  2.16 23.625 21.6 23.895 ;
     RECT  2.16 24.165 21.6 24.435 ;
     RECT  2.16 24.705 21.6 24.975 ;
     RECT  2.16 25.245 21.6 25.515 ;
     RECT  2.16 25.785 21.6 26.055 ;
     RECT  2.16 26.325 21.6 26.595 ;
     RECT  2.16 26.865 21.6 27.135 ;
     RECT  2.16 27.405 21.6 27.675 ;
     RECT  2.16 27.945 21.6 28.08 ;
    LAYER RVTP ;
     RECT  2.16 2.295 21.6 2.565 ;
     RECT  2.16 2.835 21.6 3.105 ;
     RECT  2.16 3.375 21.6 3.645 ;
     RECT  2.16 3.915 21.6 4.185 ;
     RECT  2.16 4.455 21.6 4.725 ;
     RECT  2.16 4.995 21.6 5.265 ;
     RECT  2.16 5.535 21.6 5.805 ;
     RECT  2.16 6.075 21.6 6.345 ;
     RECT  2.16 6.615 21.6 6.885 ;
     RECT  2.16 7.155 21.6 7.425 ;
     RECT  2.16 7.695 21.6 7.965 ;
     RECT  2.16 8.235 21.6 8.505 ;
     RECT  2.16 8.775 21.6 9.045 ;
     RECT  2.16 9.315 21.6 9.585 ;
     RECT  2.16 9.855 21.6 10.125 ;
     RECT  2.16 10.395 21.6 10.665 ;
     RECT  2.16 10.935 21.6 11.205 ;
     RECT  2.16 11.475 21.6 11.745 ;
     RECT  2.16 12.015 21.6 12.285 ;
     RECT  2.16 12.555 21.6 12.825 ;
     RECT  2.16 13.095 21.6 13.365 ;
     RECT  2.16 13.635 21.6 13.905 ;
     RECT  2.16 14.175 21.6 14.445 ;
     RECT  2.16 14.715 21.6 14.985 ;
     RECT  2.16 15.255 21.6 15.525 ;
     RECT  2.16 15.795 21.6 16.065 ;
     RECT  2.16 16.335 21.6 16.605 ;
     RECT  2.16 16.875 21.6 17.145 ;
     RECT  2.16 17.415 21.6 17.685 ;
     RECT  2.16 17.955 21.6 18.225 ;
     RECT  2.16 18.495 21.6 18.765 ;
     RECT  2.16 19.035 21.6 19.305 ;
     RECT  2.16 19.575 21.6 19.845 ;
     RECT  2.16 20.115 21.6 20.385 ;
     RECT  2.16 20.655 21.6 20.925 ;
     RECT  2.16 21.195 21.6 21.465 ;
     RECT  2.16 21.735 21.6 22.005 ;
     RECT  2.16 22.275 21.6 22.545 ;
     RECT  2.16 22.815 21.6 23.085 ;
     RECT  2.16 23.355 21.6 23.625 ;
     RECT  2.16 23.895 21.6 24.165 ;
     RECT  2.16 24.435 21.6 24.705 ;
     RECT  2.16 24.975 21.6 25.245 ;
     RECT  2.16 25.515 21.6 25.785 ;
     RECT  2.16 26.055 21.6 26.325 ;
     RECT  2.16 26.595 21.6 26.865 ;
     RECT  2.16 27.135 21.6 27.405 ;
     RECT  2.16 27.675 21.6 27.945 ;
    LAYER M1 ;
     RECT  2.16 2.151 21.6 28.089 ;
    LAYER M2 ;
     RECT  0.031 22.716 0.103 22.734 ;
     RECT  0.031 24.138 0.103 24.156 ;
     RECT  0.103 22.716 0.131 24.156 ;
     RECT  0.103 5.274 0.139 5.292 ;
     RECT  0.103 6.246 0.139 6.264 ;
     RECT  0.103 14.796 0.139 15.21 ;
     RECT  0.103 21.006 0.139 21.609 ;
     RECT  0.103 3.816 0.175 3.834 ;
     RECT  0.139 21.006 0.175 21.834 ;
     RECT  0.103 13.104 0.203 13.392 ;
     RECT  0.103 16.65 0.203 17.064 ;
     RECT  0.131 22.716 0.203 23.814 ;
     RECT  0.103 27.108 0.203 27.126 ;
     RECT  0.203 13.374 0.211 13.392 ;
     RECT  0.139 14.796 0.239 15.894 ;
     RECT  0.175 20.556 0.383 21.834 ;
     RECT  0.203 22.716 0.391 23.724 ;
     RECT  0.103 19.044 0.499 19.638 ;
     RECT  0.175 3.546 0.535 3.834 ;
     RECT  0.499 8.856 0.535 8.874 ;
     RECT  0.463 11.25 0.535 11.268 ;
     RECT  0.211 12.33 0.535 12.348 ;
     RECT  0.499 18.774 0.535 19.638 ;
     RECT  0.499 25.596 0.535 25.614 ;
     RECT  0.383 20.556 1.399 21.024 ;
     RECT  0.391 22.176 1.399 23.724 ;
     RECT  0.535 25.254 1.723 25.614 ;
     RECT  0.535 3.546 2.16 4.482 ;
     RECT  0.139 5.274 2.16 6.264 ;
     RECT  0.535 8.856 2.16 9.072 ;
     RECT  0.535 10.746 2.16 11.268 ;
     RECT  0.535 12.33 2.16 12.546 ;
     RECT  0.211 13.374 2.16 13.734 ;
     RECT  0.239 14.796 2.16 15.354 ;
     RECT  0.203 16.884 2.16 17.064 ;
     RECT  0.535 18.198 2.16 19.674 ;
     RECT  1.399 20.556 2.16 23.724 ;
     RECT  1.723 24.714 2.16 25.614 ;
     RECT  0.535 26.676 2.16 26.694 ;
     RECT  2.16 2.151 3.127 28.089 ;
     RECT  3.127 2.106 3.163 28.089 ;
     RECT  3.163 2.07 3.379 28.089 ;
     RECT  3.379 1.998 5.495 28.089 ;
     RECT  5.495 2.151 5.863 28.089 ;
     RECT  5.863 2.151 6.295 28.782 ;
     RECT  7.159 1.116 7.303 1.134 ;
     RECT  6.295 2.151 7.303 29.088 ;
     RECT  7.303 1.116 8.527 29.088 ;
     RECT  8.527 1.071 11.011 29.088 ;
     RECT  11.011 1.071 11.407 29.124 ;
     RECT  11.407 0.954 14.819 29.124 ;
     RECT  14.819 1.026 16.943 29.124 ;
     RECT  16.943 2.151 17.555 29.124 ;
     RECT  16.943 1.026 18.059 1.359 ;
     RECT  18.059 1.116 18.275 1.359 ;
     RECT  18.275 1.116 18.347 1.17 ;
     RECT  17.555 2.151 18.347 29.088 ;
     RECT  18.347 2.151 18.383 28.71 ;
     RECT  18.383 2.151 19.175 28.674 ;
     RECT  19.175 2.151 19.795 28.242 ;
     RECT  18.347 1.116 20.003 1.134 ;
     RECT  19.795 1.881 20.111 28.242 ;
     RECT  20.111 2.151 20.219 28.242 ;
     RECT  20.219 2.151 20.291 28.134 ;
     RECT  20.291 2.151 21.163 28.089 ;
     RECT  21.163 2.106 21.515 28.089 ;
     RECT  21.515 2.151 21.6 28.089 ;
     RECT  21.6 6.822 22.271 8.496 ;
     RECT  21.6 13.338 22.271 17.676 ;
     RECT  22.271 16.848 22.703 17.676 ;
     RECT  21.6 2.268 22.739 2.286 ;
     RECT  21.6 4.428 22.739 4.716 ;
     RECT  21.6 5.778 22.739 5.796 ;
     RECT  22.271 7.398 22.739 8.496 ;
     RECT  21.6 9.288 22.739 12.546 ;
     RECT  22.271 13.338 22.739 15.786 ;
     RECT  22.703 16.848 22.739 17.406 ;
     RECT  21.6 21.708 22.739 23.076 ;
     RECT  22.739 16.848 22.775 16.974 ;
     RECT  22.739 4.428 22.811 4.446 ;
     RECT  22.739 7.668 22.811 8.226 ;
     RECT  22.739 9.288 22.811 9.846 ;
     RECT  22.739 11.178 22.811 12.546 ;
     RECT  22.775 16.848 22.811 16.866 ;
     RECT  22.603 26.136 22.811 26.154 ;
     RECT  22.811 11.178 23.603 11.196 ;
     RECT  22.811 12.141 23.603 12.159 ;
     RECT  21.6 23.868 23.639 23.886 ;
     RECT  23.575 3.501 23.675 3.519 ;
     RECT  23.575 6.12 23.675 6.138 ;
     RECT  22.811 9.828 23.675 9.846 ;
     RECT  23.575 15.768 23.675 15.786 ;
     RECT  23.575 18.351 23.675 18.369 ;
     RECT  22.739 21.708 23.675 21.726 ;
    LAYER M3 ;
     RECT  20.484 0.331 20.502 0.475 ;
     RECT  6.732 0.331 6.75 0.811 ;
     RECT  10.008 0.475 10.026 0.859 ;
     RECT  11.268 0.379 11.286 0.949 ;
     RECT  14.652 0.427 14.67 0.949 ;
     RECT  15.876 0.859 15.894 1.003 ;
     RECT  18.252 0.811 18.27 1.021 ;
     RECT  8.136 0.427 8.154 1.066 ;
     RECT  14.652 0.949 14.814 1.066 ;
     RECT  6.048 0.811 6.75 1.111 ;
     RECT  20.412 0.475 20.502 1.111 ;
     RECT  18.036 1.021 18.27 1.147 ;
     RECT  12.348 1.021 12.366 1.195 ;
     RECT  9.504 0.859 10.026 1.291 ;
     RECT  12.276 1.195 12.366 1.291 ;
     RECT  14.652 1.066 15.138 1.291 ;
     RECT  15.876 1.003 16.398 1.291 ;
     RECT  12.276 1.291 12.69 1.336 ;
     RECT  13.68 1.021 13.698 1.336 ;
     RECT  11.268 0.949 11.43 1.381 ;
     RECT  12.276 1.336 13.698 1.381 ;
     RECT  14.652 1.291 16.398 1.381 ;
     RECT  9.504 1.291 10.242 1.489 ;
     RECT  11.268 1.381 13.698 1.489 ;
     RECT  14.652 1.381 16.434 1.489 ;
     RECT  17.28 0.379 17.298 1.489 ;
     RECT  6.048 1.111 7.182 1.525 ;
     RECT  14.652 1.489 17.298 1.606 ;
     RECT  9.504 1.489 13.698 1.627 ;
     RECT  14.58 1.606 17.298 1.627 ;
     RECT  9.504 1.627 17.298 1.723 ;
     RECT  18.036 1.147 18.342 1.723 ;
     RECT  19.98 1.111 20.502 1.723 ;
     RECT  8.136 1.066 8.55 1.759 ;
     RECT  9.504 1.723 18.342 1.759 ;
     RECT  19.98 1.723 20.826 1.819 ;
     RECT  19.872 1.819 20.826 1.867 ;
     RECT  8.136 1.759 18.342 1.963 ;
     RECT  6.048 1.525 7.326 1.993 ;
     RECT  19.8 1.867 20.826 2.011 ;
     RECT  8.136 1.963 18.774 2.059 ;
     RECT  3.384 1.993 3.402 2.065 ;
     RECT  3.168 2.065 3.402 2.101 ;
     RECT  4.644 2.065 4.662 2.101 ;
     RECT  5.472 1.993 7.326 2.101 ;
     RECT  19.8 2.011 20.97 2.101 ;
     RECT  3.132 2.101 3.402 2.143 ;
     RECT  4.644 2.101 7.326 2.143 ;
     RECT  8.136 2.059 18.954 2.143 ;
     RECT  2.415 2.143 3.402 2.227 ;
     RECT  22.716 1.867 22.734 2.291 ;
     RECT  2.415 2.227 3.798 2.299 ;
     RECT  4.644 2.143 18.954 2.299 ;
     RECT  19.8 2.101 21.51 2.299 ;
     RECT  2.415 2.299 21.51 2.335 ;
     RECT  22.788 3.163 22.806 3.211 ;
     RECT  22.68 3.211 22.806 3.341 ;
     RECT  22.788 3.341 22.806 3.403 ;
     RECT  22.788 3.403 23.454 3.451 ;
     RECT  22.788 3.451 23.598 3.496 ;
     RECT  22.788 3.496 23.67 3.533 ;
     RECT  0.18 3.541 0.198 3.643 ;
     RECT  0.144 3.643 0.198 3.811 ;
     RECT  0.108 3.811 0.198 3.955 ;
     RECT  0.108 3.955 0.558 4.075 ;
     RECT  0.108 4.075 0.702 4.205 ;
     RECT  22.788 3.533 23.49 4.205 ;
     RECT  0.108 4.205 0.63 4.289 ;
     RECT  22.788 4.205 22.806 4.451 ;
     RECT  22.716 4.555 22.734 4.721 ;
     RECT  0.108 4.289 0.558 5.069 ;
     RECT  2.304 2.335 21.51 5.297 ;
     RECT  22.716 5.707 22.734 5.801 ;
     RECT  0.108 5.069 0.162 5.803 ;
     RECT  2.304 5.297 21.402 6.035 ;
     RECT  23.58 4.315 23.598 6.091 ;
     RECT  23.58 6.091 23.67 6.143 ;
     RECT  0.108 5.803 0.342 6.151 ;
     RECT  0.108 6.151 0.558 6.317 ;
     RECT  0.54 6.317 0.558 6.605 ;
     RECT  23.58 6.143 23.598 6.701 ;
     RECT  22.248 6.571 22.266 6.845 ;
     RECT  2.304 6.035 21.222 7.195 ;
     RECT  2.304 7.195 21.258 7.325 ;
     RECT  22.716 6.955 22.734 7.421 ;
     RECT  22.788 7.627 22.806 8.231 ;
     RECT  2.304 7.325 21.114 8.401 ;
     RECT  22.716 8.395 22.734 8.501 ;
     RECT  0.144 7.243 0.162 8.587 ;
     RECT  0.144 8.587 0.45 8.813 ;
     RECT  2.304 8.401 21.402 8.969 ;
     RECT  0.504 8.851 0.522 9.049 ;
     RECT  22.788 9.259 22.806 9.311 ;
     RECT  0.504 9.049 0.558 9.485 ;
     RECT  0.504 9.485 0.522 9.773 ;
     RECT  23.652 9.643 23.67 9.851 ;
     RECT  2.304 8.969 21.33 10.201 ;
     RECT  2.304 10.201 21.402 10.219 ;
     RECT  1.98 10.219 21.402 10.349 ;
     RECT  22.716 10.027 22.734 10.661 ;
     RECT  2.304 10.349 21.402 11.039 ;
     RECT  23.58 10.795 23.598 11.201 ;
     RECT  0.54 10.741 0.558 11.245 ;
     RECT  2.304 11.039 21.33 11.281 ;
     RECT  2.268 11.281 21.33 11.399 ;
     RECT  2.268 11.399 21.258 11.563 ;
     RECT  1.98 11.563 21.258 11.741 ;
     RECT  22.788 11.467 22.806 12.043 ;
     RECT  22.788 12.043 23.454 12.136 ;
     RECT  22.788 12.136 23.598 12.173 ;
     RECT  22.788 12.173 23.49 12.269 ;
     RECT  0.468 11.245 0.558 12.325 ;
     RECT  2.268 11.741 21.258 12.379 ;
     RECT  22.788 12.269 22.806 12.551 ;
     RECT  0.216 12.325 0.558 12.557 ;
     RECT  2.268 12.379 21.762 12.557 ;
     RECT  2.268 12.557 21.402 12.811 ;
     RECT  2.196 12.811 21.402 12.859 ;
     RECT  0.216 12.557 0.234 12.907 ;
     RECT  2.124 12.859 21.402 13.037 ;
     RECT  0.144 12.907 0.234 13.084 ;
     RECT  22.716 13.099 22.734 13.387 ;
     RECT  0.108 13.084 0.234 13.771 ;
     RECT  22.68 13.387 22.734 13.867 ;
     RECT  0.108 13.771 0.342 13.901 ;
     RECT  22.248 13.867 22.734 14.243 ;
     RECT  2.304 13.037 21.402 14.449 ;
     RECT  2.268 14.449 21.402 14.573 ;
     RECT  0.144 13.901 0.234 14.791 ;
     RECT  0.108 14.791 0.234 14.827 ;
     RECT  2.376 14.573 21.402 14.909 ;
     RECT  0.108 14.827 0.342 15.061 ;
     RECT  0.108 15.061 0.558 15.533 ;
     RECT  2.376 14.909 21.258 15.592 ;
     RECT  2.304 15.592 21.258 15.629 ;
     RECT  23.58 14.827 23.598 15.763 ;
     RECT  22.716 14.243 22.734 15.791 ;
     RECT  23.58 15.763 23.67 15.791 ;
     RECT  23.652 15.791 23.67 15.821 ;
     RECT  0.144 15.533 0.558 16.013 ;
     RECT  2.415 15.629 21.258 16.141 ;
     RECT  22.248 16.105 22.266 16.205 ;
     RECT  2.415 16.141 21.402 16.411 ;
     RECT  2.412 16.411 21.402 16.501 ;
     RECT  0.144 16.013 0.198 16.636 ;
     RECT  22.752 16.555 22.806 16.871 ;
     RECT  0.108 16.636 0.198 16.879 ;
     RECT  22.752 16.871 22.77 16.939 ;
     RECT  22.716 16.939 22.77 16.979 ;
     RECT  2.304 16.501 21.402 17.069 ;
     RECT  0.108 16.879 0.558 17.165 ;
     RECT  22.716 16.979 22.734 17.323 ;
     RECT  0.18 17.165 0.558 17.357 ;
     RECT  22.68 17.323 22.734 17.411 ;
     RECT  22.68 17.411 22.698 17.681 ;
     RECT  2.304 17.069 21.33 17.761 ;
     RECT  0.144 17.947 0.162 18.125 ;
     RECT  2.268 17.761 21.33 18.193 ;
     RECT  23.58 18.331 23.598 18.346 ;
     RECT  23.58 18.346 23.67 18.374 ;
     RECT  23.652 18.374 23.67 18.413 ;
     RECT  2.268 18.193 21.402 18.599 ;
     RECT  0.504 18.193 0.558 18.605 ;
     RECT  0.504 18.605 0.522 18.859 ;
     RECT  0.144 18.859 0.522 19.036 ;
     RECT  2.34 18.599 21.402 19.381 ;
     RECT  0.108 19.036 0.522 19.651 ;
     RECT  0.108 19.651 0.558 19.757 ;
     RECT  0.18 19.757 0.558 19.805 ;
     RECT  0.432 19.805 0.558 20.551 ;
     RECT  0.18 20.551 0.558 20.923 ;
     RECT  0.144 20.923 0.558 21.001 ;
     RECT  23.58 20.683 23.598 21.053 ;
     RECT  2.304 19.381 21.402 21.299 ;
     RECT  0.108 21.001 0.558 21.389 ;
     RECT  0.108 21.389 0.378 21.614 ;
     RECT  23.652 21.547 23.67 21.731 ;
     RECT  2.34 21.299 21.402 22.081 ;
     RECT  0.144 21.614 0.378 22.171 ;
     RECT  2.304 22.081 21.402 22.649 ;
     RECT  0.144 22.171 0.414 22.711 ;
     RECT  22.716 21.835 22.734 23.081 ;
     RECT  2.34 22.649 21.402 23.261 ;
     RECT  2.34 23.261 21.366 23.395 ;
     RECT  0.036 22.711 0.414 23.629 ;
     RECT  1.404 21.631 1.422 23.803 ;
     RECT  2.232 23.395 21.366 23.803 ;
     RECT  23.472 23.755 23.49 23.851 ;
     RECT  23.472 23.851 23.634 23.885 ;
     RECT  23.616 23.885 23.634 23.891 ;
     RECT  0.036 23.629 0.558 24.161 ;
     RECT  1.404 23.803 21.366 24.173 ;
     RECT  1.728 24.173 21.366 24.469 ;
     RECT  1.728 24.469 21.474 24.509 ;
     RECT  1.728 24.509 21.438 24.737 ;
     RECT  2.304 24.737 21.438 24.899 ;
     RECT  0.108 24.161 0.558 25.325 ;
     RECT  0.144 25.325 0.558 25.805 ;
     RECT  23.58 25.675 23.598 26.045 ;
     RECT  22.68 26.059 22.698 26.107 ;
     RECT  22.608 26.107 22.698 26.131 ;
     RECT  22.608 26.131 22.806 26.159 ;
     RECT  22.68 26.159 22.806 26.189 ;
     RECT  2.304 24.899 21.402 26.365 ;
     RECT  2.304 26.365 21.438 26.477 ;
     RECT  2.34 26.477 21.438 26.555 ;
     RECT  0.144 25.805 0.522 26.671 ;
     RECT  0.144 26.671 0.558 27.1 ;
     RECT  0.108 27.1 0.558 27.245 ;
     RECT  2.34 26.555 15.57 27.355 ;
     RECT  1.98 27.355 15.57 27.533 ;
     RECT  2.304 27.533 15.57 27.547 ;
     RECT  2.304 27.547 15.606 27.599 ;
     RECT  16.416 26.555 21.438 27.599 ;
     RECT  2.415 27.599 15.534 27.743 ;
     RECT  2.415 27.743 14.598 27.773 ;
     RECT  16.416 27.599 21.402 27.779 ;
     RECT  2.415 27.773 9.018 27.821 ;
     RECT  9.936 27.773 14.598 27.827 ;
     RECT  2.415 27.821 8.946 27.869 ;
     RECT  14.112 27.827 14.598 27.869 ;
     RECT  15.408 27.743 15.534 27.869 ;
     RECT  21.24 27.779 21.402 27.869 ;
     RECT  15.516 27.869 15.534 27.905 ;
     RECT  21.24 27.869 21.258 27.905 ;
     RECT  2.415 27.869 2.754 27.917 ;
     RECT  9.936 27.827 13.374 27.917 ;
     RECT  16.416 27.779 20.502 27.917 ;
     RECT  12.636 27.917 13.374 27.941 ;
     RECT  10.836 27.917 11.898 27.965 ;
     RECT  14.328 27.869 14.598 27.965 ;
     RECT  9.936 27.917 10.098 27.977 ;
     RECT  0.54 27.245 0.558 27.979 ;
     RECT  0.54 27.979 0.666 28.013 ;
     RECT  3.888 27.869 8.946 28.049 ;
     RECT  2.415 27.917 2.505 28.097 ;
     RECT  0.648 28.013 0.666 28.109 ;
     RECT  13.176 27.941 13.374 28.139 ;
     RECT  4.32 28.049 8.946 28.157 ;
     RECT  4.32 28.157 8.766 28.205 ;
     RECT  14.436 27.965 14.598 28.205 ;
     RECT  8.748 28.205 8.766 28.211 ;
     RECT  13.356 28.139 13.374 28.283 ;
     RECT  16.92 27.917 20.502 28.301 ;
     RECT  14.544 28.205 14.598 28.349 ;
     RECT  14.58 28.349 14.598 28.489 ;
     RECT  14.58 28.489 14.67 28.517 ;
     RECT  16.92 28.301 20.43 28.541 ;
     RECT  20.412 28.541 20.43 28.589 ;
     RECT  4.32 28.205 7.686 28.634 ;
     RECT  4.32 28.634 7.398 28.637 ;
     RECT  9.972 27.977 10.098 28.679 ;
     RECT  16.92 28.541 19.53 28.685 ;
     RECT  9.972 28.679 9.99 28.715 ;
     RECT  14.652 28.517 14.67 28.723 ;
     RECT  16.92 28.685 18.99 28.733 ;
     RECT  7.38 28.637 7.398 28.751 ;
     RECT  10.836 27.965 11.754 28.751 ;
     RECT  14.652 28.723 14.742 28.751 ;
     RECT  16.92 28.733 18.342 28.751 ;
     RECT  16.92 28.751 17.55 28.787 ;
     RECT  10.836 28.751 11.034 28.823 ;
     RECT  14.724 28.751 14.742 28.823 ;
     RECT  4.32 28.637 6.318 29.069 ;
     RECT  5.292 29.069 6.318 29.093 ;
     RECT  18.324 28.751 18.342 29.093 ;
     RECT  11.016 28.823 11.034 29.129 ;
     RECT  17.532 28.787 17.55 29.129 ;
     RECT  4.32 29.069 4.446 29.165 ;
     RECT  4.428 29.165 4.446 29.261 ;
     RECT  5.292 29.093 5.634 29.357 ;
     RECT  5.292 29.357 5.31 29.453 ;
    LAYER M4 ;
     RECT  0.06 3.216 2.408 29.448 ;
     RECT  2.408 2.148 2.512 29.448 ;
     RECT  2.512 2.418 2.704 29.448 ;
     RECT  2.704 3.168 4.133 29.448 ;
     RECT  4.133 3.168 4.277 5.304 ;
     RECT  4.277 3.168 4.381 4.728 ;
     RECT  4.133 6.384 4.385 29.448 ;
     RECT  4.381 2.736 4.493 4.728 ;
     RECT  4.493 2.832 4.817 4.728 ;
     RECT  3.541 1.056 5.029 1.08 ;
     RECT  4.817 3.168 5.315 4.728 ;
     RECT  4.385 6.624 5.321 29.448 ;
     RECT  5.315 3.168 5.465 3.624 ;
     RECT  5.389 4.992 5.537 5.016 ;
     RECT  5.321 6.624 5.645 29.352 ;
     RECT  5.645 6.624 5.785 28.872 ;
     RECT  5.785 6 6.001 28.872 ;
     RECT  5.029 1.056 6.037 1.416 ;
     RECT  6.001 5.184 6.041 28.872 ;
     RECT  5.465 3.408 6.083 3.624 ;
     RECT  6.041 5.184 6.185 28.776 ;
     RECT  6.185 5.184 6.221 28.68 ;
     RECT  6.221 5.184 6.257 28.632 ;
     RECT  6.037 0.816 6.325 1.416 ;
     RECT  6.083 3.552 6.325 3.624 ;
     RECT  6.257 25.968 6.545 28.632 ;
     RECT  6.545 28.464 6.689 28.632 ;
     RECT  6.257 5.184 6.716 24.984 ;
     RECT  6.325 0.816 6.721 1.464 ;
     RECT  6.721 0.336 6.757 1.464 ;
     RECT  6.325 3.552 6.829 4.008 ;
     RECT  6.716 5.136 6.829 24.984 ;
     RECT  6.829 3.552 7.429 24.984 ;
     RECT  7.429 3.024 7.621 24.984 ;
     RECT  6.545 25.968 7.621 27.336 ;
     RECT  6.757 0.336 7.808 1.56 ;
     RECT  7.621 3.024 7.808 27.336 ;
     RECT  6.689 28.512 7.808 28.632 ;
     RECT  7.808 0.336 8.104 28.632 ;
     RECT  8.104 0.336 9.349 1.56 ;
     RECT  8.104 2.736 9.349 28.632 ;
     RECT  9.349 0.336 11.125 28.632 ;
     RECT  11.125 0.336 11.221 28.68 ;
     RECT  11.221 0.336 19.001 28.728 ;
     RECT  19.001 0.336 19.541 28.68 ;
     RECT  19.541 0.336 20.441 28.584 ;
     RECT  20.441 0.336 20.513 28.296 ;
     RECT  20.513 0.816 21.017 27.624 ;
     RECT  21.017 0.816 21.059 27.384 ;
     RECT  21.059 0.816 21.539 27 ;
     RECT  21.539 0.816 21.589 26.952 ;
     RECT  21.589 0.72 23.724 26.952 ;
    LAYER M5 ;
     RECT  21.6 0.709 21.624 0.805 ;
     RECT  7.68 0.901 7.704 0.949 ;
     RECT  19.824 0.901 19.848 0.997 ;
     RECT  13.728 0.517 13.752 1.045 ;
     RECT  10.224 0.517 10.248 1.093 ;
     RECT  13.728 1.045 13.8 1.093 ;
     RECT  19.056 0.997 19.848 1.189 ;
     RECT  20.976 0.805 21.624 1.189 ;
     RECT  10.224 1.093 10.824 1.237 ;
     RECT  7.488 0.949 7.704 1.333 ;
     RECT  15.552 0.901 15.576 1.381 ;
     RECT  19.056 1.189 21.624 1.429 ;
     RECT  15.552 1.381 16.152 1.477 ;
     RECT  17.328 0.949 17.352 1.477 ;
     RECT  6.336 1.429 6.36 1.525 ;
     RECT  7.488 1.333 8.52 1.525 ;
     RECT  13.728 1.093 13.896 1.573 ;
     RECT  10.224 1.237 11.304 1.621 ;
     RECT  12.96 1.573 13.896 1.669 ;
     RECT  12.96 1.669 14.328 1.717 ;
     RECT  15.552 1.477 17.352 1.717 ;
     RECT  12.96 1.717 17.352 1.957 ;
     RECT  19.008 1.429 21.624 1.957 ;
     RECT  2.4 2.137 2.52 2.151 ;
     RECT  3.552 1.045 3.576 2.151 ;
     RECT  12.912 1.957 17.352 2.245 ;
     RECT  18.432 1.957 21.624 2.245 ;
     RECT  12.624 2.245 17.352 2.629 ;
     RECT  12.528 2.629 17.352 2.725 ;
     RECT  18.432 2.245 21.672 2.725 ;
     RECT  10.032 1.621 11.304 2.773 ;
     RECT  12.528 2.725 21.672 2.773 ;
     RECT  10.032 2.773 21.672 2.821 ;
     RECT  6.336 1.525 8.52 3.397 ;
     RECT  9.648 2.821 21.672 3.539 ;
     RECT  9.696 3.539 21.672 3.779 ;
     RECT  9.936 3.779 21.672 4.019 ;
     RECT  5.04 1.381 5.064 4.261 ;
     RECT  6.048 3.397 8.52 4.261 ;
     RECT  9.936 4.019 21.096 4.451 ;
     RECT  23.568 4.165 23.592 4.451 ;
     RECT  0.144 4.309 0.168 4.499 ;
     RECT  5.04 4.261 8.52 4.595 ;
     RECT  11.28 4.451 21.096 4.835 ;
     RECT  11.28 4.835 20.52 5.027 ;
     RECT  9.936 4.451 10.056 6.037 ;
     RECT  9.936 6.037 10.2 6.181 ;
     RECT  11.28 5.027 11.304 6.181 ;
     RECT  12.672 5.027 20.52 6.371 ;
     RECT  12.672 6.371 19.944 6.805 ;
     RECT  21.072 6.373 21.096 6.947 ;
     RECT  9.936 6.181 11.304 7.285 ;
     RECT  12.528 6.805 19.944 7.285 ;
     RECT  9.936 7.285 19.944 7.381 ;
     RECT  9.936 7.381 20.808 7.763 ;
     RECT  9.936 7.763 20.52 9.013 ;
     RECT  9.936 9.013 21 9.349 ;
     RECT  9.84 9.349 21 9.925 ;
     RECT  2.4 2.151 3.576 10.165 ;
     RECT  5.28 4.595 8.52 10.165 ;
     RECT  9.84 9.925 21.672 10.165 ;
     RECT  2.4 10.165 3.96 10.355 ;
     RECT  5.28 10.165 21.672 11.075 ;
     RECT  5.28 11.075 11.304 11.459 ;
     RECT  12.576 11.075 21.672 11.459 ;
     RECT  23.568 12.085 23.592 12.275 ;
     RECT  2.4 10.355 3.576 12.563 ;
     RECT  21.6 11.459 21.672 12.563 ;
     RECT  12.576 11.459 20.472 12.757 ;
     RECT  9.84 11.459 11.304 13.285 ;
     RECT  12.576 12.757 21.096 13.285 ;
     RECT  9.84 13.285 21.096 14.339 ;
     RECT  5.28 11.459 8.52 14.533 ;
     RECT  9.84 14.339 20.52 15.397 ;
     RECT  0.144 15.541 0.168 15.827 ;
     RECT  5.28 14.533 8.856 16.019 ;
     RECT  9.84 15.397 21.096 16.453 ;
     RECT  9.84 16.453 21.672 16.595 ;
     RECT  0.192 16.405 0.216 16.643 ;
     RECT  9.84 16.595 20.52 16.643 ;
     RECT  9.84 16.643 15.72 17.605 ;
     RECT  16.752 16.643 20.52 17.605 ;
     RECT  21.648 16.595 21.672 17.699 ;
     RECT  9.84 17.605 20.52 17.989 ;
     RECT  21.552 17.701 21.576 17.989 ;
     RECT  5.28 16.019 8.52 18.181 ;
     RECT  9.84 17.989 21.576 18.181 ;
     RECT  5.28 18.181 21.576 19.379 ;
     RECT  16.752 19.379 21.576 19.427 ;
     RECT  16.752 19.427 21.336 19.715 ;
     RECT  5.28 19.379 15.72 19.859 ;
     RECT  16.848 19.715 21.336 20.677 ;
     RECT  16.656 20.677 21.336 21.011 ;
     RECT  16.944 21.011 21.336 21.107 ;
     RECT  16.944 21.107 21.192 21.827 ;
     RECT  16.944 21.827 20.76 22.259 ;
     RECT  5.28 19.859 15.672 22.835 ;
     RECT  20.736 22.259 20.76 23.221 ;
     RECT  16.944 22.259 19.752 23.317 ;
     RECT  20.736 23.221 21.048 23.317 ;
     RECT  16.944 23.317 21.048 23.461 ;
     RECT  12.768 22.835 15.672 23.797 ;
     RECT  16.8 23.461 21.048 23.797 ;
     RECT  0.144 23.653 0.168 23.843 ;
     RECT  12.768 23.797 21.048 24.229 ;
     RECT  12.768 24.229 21.096 24.517 ;
     RECT  12.768 24.517 21.672 24.563 ;
     RECT  5.28 22.835 11.304 25.045 ;
     RECT  12.768 24.563 16.968 25.139 ;
     RECT  5.28 25.045 11.544 25.475 ;
     RECT  5.28 25.475 11.304 25.907 ;
     RECT  18.192 24.563 21.672 25.955 ;
     RECT  20.112 25.955 21.672 26.099 ;
     RECT  20.16 26.099 21.672 26.243 ;
     RECT  13.2 25.139 16.968 26.341 ;
     RECT  18.192 25.955 18.912 26.341 ;
     RECT  5.28 25.907 8.28 26.435 ;
     RECT  9.84 25.907 11.304 26.533 ;
     RECT  13.104 26.341 18.912 26.579 ;
     RECT  13.2 26.579 18.912 26.819 ;
     RECT  20.16 26.243 21.624 26.819 ;
     RECT  18.144 26.819 18.912 26.867 ;
     RECT  20.16 26.819 21.576 26.915 ;
     RECT  20.16 26.915 21.528 27.011 ;
     RECT  15.12 26.819 15.912 27.155 ;
     RECT  5.28 26.435 5.304 27.299 ;
     RECT  20.16 27.011 21.048 27.395 ;
     RECT  20.16 27.395 21 27.443 ;
     RECT  3.936 27.349 3.96 27.491 ;
     RECT  6.864 26.435 8.28 27.491 ;
     RECT  15.12 27.155 15.672 27.491 ;
     RECT  20.976 27.443 21 27.491 ;
     RECT  9.84 26.533 11.688 27.539 ;
     RECT  13.2 26.819 13.944 27.539 ;
     RECT  9.936 27.539 11.688 27.635 ;
     RECT  18.192 26.867 18.912 27.635 ;
     RECT  15.12 27.491 15.144 27.683 ;
     RECT  9.936 27.635 11.256 27.731 ;
     RECT  16.944 26.819 16.968 27.829 ;
     RECT  10.224 27.731 11.256 27.971 ;
     RECT  2.4 12.563 2.712 28.089 ;
     RECT  6.864 27.491 8.112 28.089 ;
     RECT  13.2 27.539 13.512 28.089 ;
     RECT  18.6 27.635 18.912 28.089 ;
     RECT  2.4 28.089 2.52 28.103 ;
     RECT  6.864 28.089 7.92 28.103 ;
     RECT  13.2 28.089 13.32 28.103 ;
     RECT  18.6 28.089 18.72 28.103 ;
     RECT  11.136 27.971 11.256 28.259 ;
     RECT  6.864 28.103 6.888 28.595 ;
     RECT  11.136 28.259 11.16 28.691 ;
     RECT  16.944 27.829 17.064 30.224 ;
     RECT  19.848 0.901 20.976 1.189 ;
     RECT  3.576 1.381 5.04 4.595 ;
     RECT  16.152 1.381 17.328 1.477 ;
     RECT  5.064 1.429 6.336 3.397 ;
     RECT  6.36 1.429 7.488 1.525 ;
     RECT  8.52 1.621 10.032 2.821 ;
     RECT  14.328 1.669 15.552 1.717 ;
     RECT  17.352 1.957 18.432 2.725 ;
     RECT  2.52 2.137 3.552 2.151 ;
     RECT  11.304 2.245 12.624 2.629 ;
     RECT  11.304 2.629 12.528 2.773 ;
     RECT  8.52 2.821 9.648 3.539 ;
     RECT  5.064 3.397 6.048 4.261 ;
     RECT  8.52 3.539 9.696 3.779 ;
     RECT  8.52 3.779 9.936 9.349 ;
     RECT  10.056 4.451 11.28 6.037 ;
     RECT  11.304 5.027 12.672 6.805 ;
     RECT  10.2 6.037 11.28 6.181 ;
     RECT  19.944 6.371 20.52 6.373 ;
     RECT  19.944 6.373 21.072 6.947 ;
     RECT  11.304 6.805 12.528 7.285 ;
     RECT  19.944 6.947 20.808 7.381 ;
     RECT  20.52 7.763 20.808 9.013 ;
     RECT  8.52 9.349 9.84 10.165 ;
     RECT  3.96 10.165 5.28 10.355 ;
     RECT  11.304 11.075 12.576 13.285 ;
     RECT  8.52 11.459 9.84 14.533 ;
     RECT  20.472 11.459 21.6 12.563 ;
     RECT  20.472 12.563 21.096 12.757 ;
     RECT  20.52 14.339 21.096 15.397 ;
     RECT  8.856 14.533 9.84 16.019 ;
     RECT  8.52 16.019 9.84 18.181 ;
     RECT  20.52 16.595 21.648 17.699 ;
     RECT  15.72 16.643 16.752 17.605 ;
     RECT  20.52 17.699 21.576 17.701 ;
     RECT  20.52 17.701 21.552 17.989 ;
     RECT  15.72 19.379 16.752 19.715 ;
     RECT  15.72 19.715 16.848 19.859 ;
     RECT  15.672 19.859 16.848 20.677 ;
     RECT  15.672 20.677 16.656 21.011 ;
     RECT  15.672 21.011 16.944 23.461 ;
     RECT  20.76 21.827 21.048 23.221 ;
     RECT  19.752 22.259 20.736 23.317 ;
     RECT  11.304 22.835 12.768 25.045 ;
     RECT  15.672 23.461 16.8 23.797 ;
     RECT  16.968 24.563 18.192 26.341 ;
     RECT  11.544 25.045 12.768 25.139 ;
     RECT  11.544 25.139 13.2 25.475 ;
     RECT  11.304 25.475 13.2 26.341 ;
     RECT  18.912 25.955 20.112 26.099 ;
     RECT  18.912 26.099 20.16 27.443 ;
     RECT  11.304 26.341 13.104 26.533 ;
     RECT  11.688 26.533 13.104 26.579 ;
     RECT  11.688 26.579 13.2 27.635 ;
     RECT  13.944 26.819 15.12 27.539 ;
     RECT  15.912 26.819 16.944 27.155 ;
     RECT  16.968 26.819 18.144 26.867 ;
     RECT  16.968 26.867 18.192 27.635 ;
     RECT  15.672 27.155 16.944 27.491 ;
     RECT  2.712 27.349 3.936 27.491 ;
     RECT  16.968 27.635 17.064 27.829 ;
  END
END dsfd_rly_266_EW
END LIBRARY
